VERSION 5.7 ;
BUSBITCHARS "[]" ;
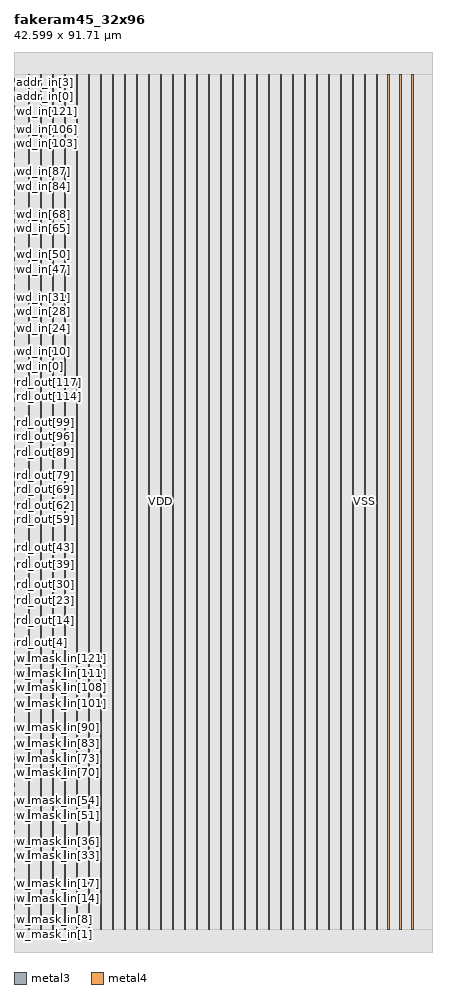
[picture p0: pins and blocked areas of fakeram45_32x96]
MACRO fakeram45_32x96
  FOREIGN fakeram45_32x96 0 0 ;
  SYMMETRY X Y R90 ;
  SIZE 42.599 BY 91.710 ;
  CLASS BLOCK ;
  PIN w_mask_in[0]
    DIRECTION INPUT ;
    USE SIGNAL ;
    SHAPE ABUTMENT ;
    PORT
      LAYER metal3 ;
      RECT 0.000 2.280 0.038 2.338 ;
    END
  END w_mask_in[0]
  PIN w_mask_in[1]
    DIRECTION INPUT ;
    USE SIGNAL ;
    SHAPE ABUTMENT ;
    PORT
      LAYER metal3 ;
      RECT 0.000 2.508 0.038 2.566 ;
    END
  END w_mask_in[1]
  PIN w_mask_in[2]
    DIRECTION INPUT ;
    USE SIGNAL ;
    SHAPE ABUTMENT ;
    PORT
      LAYER metal3 ;
      RECT 0.000 2.736 0.038 2.794 ;
    END
  END w_mask_in[2]
  PIN w_mask_in[3]
    DIRECTION INPUT ;
    USE SIGNAL ;
    SHAPE ABUTMENT ;
    PORT
      LAYER metal3 ;
      RECT 0.000 2.964 0.038 3.022 ;
    END
  END w_mask_in[3]
  PIN w_mask_in[4]
    DIRECTION INPUT ;
    USE SIGNAL ;
    SHAPE ABUTMENT ;
    PORT
      LAYER metal3 ;
      RECT 0.000 3.192 0.038 3.250 ;
    END
  END w_mask_in[4]
  PIN w_mask_in[5]
    DIRECTION INPUT ;
    USE SIGNAL ;
    SHAPE ABUTMENT ;
    PORT
      LAYER metal3 ;
      RECT 0.000 3.421 0.038 3.478 ;
    END
  END w_mask_in[5]
  PIN w_mask_in[6]
    DIRECTION INPUT ;
    USE SIGNAL ;
    SHAPE ABUTMENT ;
    PORT
      LAYER metal3 ;
      RECT 0.000 3.649 0.038 3.706 ;
    END
  END w_mask_in[6]
  PIN w_mask_in[7]
    DIRECTION INPUT ;
    USE SIGNAL ;
    SHAPE ABUTMENT ;
    PORT
      LAYER metal3 ;
      RECT 0.000 3.877 0.038 3.934 ;
    END
  END w_mask_in[7]
  PIN w_mask_in[8]
    DIRECTION INPUT ;
    USE SIGNAL ;
    SHAPE ABUTMENT ;
    PORT
      LAYER metal3 ;
      RECT 0.000 4.105 0.038 4.162 ;
    END
  END w_mask_in[8]
  PIN w_mask_in[9]
    DIRECTION INPUT ;
    USE SIGNAL ;
    SHAPE ABUTMENT ;
    PORT
      LAYER metal3 ;
      RECT 0.000 4.333 0.038 4.390 ;
    END
  END w_mask_in[9]
  PIN w_mask_in[10]
    DIRECTION INPUT ;
    USE SIGNAL ;
    SHAPE ABUTMENT ;
    PORT
      LAYER metal3 ;
      RECT 0.000 4.561 0.038 4.618 ;
    END
  END w_mask_in[10]
  PIN w_mask_in[11]
    DIRECTION INPUT ;
    USE SIGNAL ;
    SHAPE ABUTMENT ;
    PORT
      LAYER metal3 ;
      RECT 0.000 4.789 0.038 4.846 ;
    END
  END w_mask_in[11]
  PIN w_mask_in[12]
    DIRECTION INPUT ;
    USE SIGNAL ;
    SHAPE ABUTMENT ;
    PORT
      LAYER metal3 ;
      RECT 0.000 5.017 0.038 5.074 ;
    END
  END w_mask_in[12]
  PIN w_mask_in[13]
    DIRECTION INPUT ;
    USE SIGNAL ;
    SHAPE ABUTMENT ;
    PORT
      LAYER metal3 ;
      RECT 0.000 5.245 0.038 5.302 ;
    END
  END w_mask_in[13]
  PIN w_mask_in[14]
    DIRECTION INPUT ;
    USE SIGNAL ;
    SHAPE ABUTMENT ;
    PORT
      LAYER metal3 ;
      RECT 0.000 5.474 0.038 5.530 ;
    END
  END w_mask_in[14]
  PIN w_mask_in[15]
    DIRECTION INPUT ;
    USE SIGNAL ;
    SHAPE ABUTMENT ;
    PORT
      LAYER metal3 ;
      RECT 0.000 5.702 0.038 5.758 ;
    END
  END w_mask_in[15]
  PIN w_mask_in[16]
    DIRECTION INPUT ;
    USE SIGNAL ;
    SHAPE ABUTMENT ;
    PORT
      LAYER metal3 ;
      RECT 0.000 5.930 0.038 5.986 ;
    END
  END w_mask_in[16]
  PIN w_mask_in[17]
    DIRECTION INPUT ;
    USE SIGNAL ;
    SHAPE ABUTMENT ;
    PORT
      LAYER metal3 ;
      RECT 0.000 6.158 0.038 6.214 ;
    END
  END w_mask_in[17]
  PIN w_mask_in[18]
    DIRECTION INPUT ;
    USE SIGNAL ;
    SHAPE ABUTMENT ;
    PORT
      LAYER metal3 ;
      RECT 0.000 6.386 0.038 6.443 ;
    END
  END w_mask_in[18]
  PIN w_mask_in[19]
    DIRECTION INPUT ;
    USE SIGNAL ;
    SHAPE ABUTMENT ;
    PORT
      LAYER metal3 ;
      RECT 0.000 6.613 0.038 6.671 ;
    END
  END w_mask_in[19]
  PIN w_mask_in[20]
    DIRECTION INPUT ;
    USE SIGNAL ;
    SHAPE ABUTMENT ;
    PORT
      LAYER metal3 ;
      RECT 0.000 6.841 0.038 6.899 ;
    END
  END w_mask_in[20]
  PIN w_mask_in[21]
    DIRECTION INPUT ;
    USE SIGNAL ;
    SHAPE ABUTMENT ;
    PORT
      LAYER metal3 ;
      RECT 0.000 7.069 0.038 7.127 ;
    END
  END w_mask_in[21]
  PIN w_mask_in[22]
    DIRECTION INPUT ;
    USE SIGNAL ;
    SHAPE ABUTMENT ;
    PORT
      LAYER metal3 ;
      RECT 0.000 7.297 0.038 7.355 ;
    END
  END w_mask_in[22]
  PIN w_mask_in[23]
    DIRECTION INPUT ;
    USE SIGNAL ;
    SHAPE ABUTMENT ;
    PORT
      LAYER metal3 ;
      RECT 0.000 7.526 0.038 7.583 ;
    END
  END w_mask_in[23]
  PIN w_mask_in[24]
    DIRECTION INPUT ;
    USE SIGNAL ;
    SHAPE ABUTMENT ;
    PORT
      LAYER metal3 ;
      RECT 0.000 7.754 0.038 7.811 ;
    END
  END w_mask_in[24]
  PIN w_mask_in[25]
    DIRECTION INPUT ;
    USE SIGNAL ;
    SHAPE ABUTMENT ;
    PORT
      LAYER metal3 ;
      RECT 0.000 7.982 0.038 8.039 ;
    END
  END w_mask_in[25]
  PIN w_mask_in[26]
    DIRECTION INPUT ;
    USE SIGNAL ;
    SHAPE ABUTMENT ;
    PORT
      LAYER metal3 ;
      RECT 0.000 8.210 0.038 8.267 ;
    END
  END w_mask_in[26]
  PIN w_mask_in[27]
    DIRECTION INPUT ;
    USE SIGNAL ;
    SHAPE ABUTMENT ;
    PORT
      LAYER metal3 ;
      RECT 0.000 8.438 0.038 8.495 ;
    END
  END w_mask_in[27]
  PIN w_mask_in[28]
    DIRECTION INPUT ;
    USE SIGNAL ;
    SHAPE ABUTMENT ;
    PORT
      LAYER metal3 ;
      RECT 0.000 8.666 0.038 8.723 ;
    END
  END w_mask_in[28]
  PIN w_mask_in[29]
    DIRECTION INPUT ;
    USE SIGNAL ;
    SHAPE ABUTMENT ;
    PORT
      LAYER metal3 ;
      RECT 0.000 8.894 0.038 8.951 ;
    END
  END w_mask_in[29]
  PIN w_mask_in[30]
    DIRECTION INPUT ;
    USE SIGNAL ;
    SHAPE ABUTMENT ;
    PORT
      LAYER metal3 ;
      RECT 0.000 9.122 0.038 9.179 ;
    END
  END w_mask_in[30]
  PIN w_mask_in[31]
    DIRECTION INPUT ;
    USE SIGNAL ;
    SHAPE ABUTMENT ;
    PORT
      LAYER metal3 ;
      RECT 0.000 9.350 0.038 9.407 ;
    END
  END w_mask_in[31]
  PIN w_mask_in[32]
    DIRECTION INPUT ;
    USE SIGNAL ;
    SHAPE ABUTMENT ;
    PORT
      LAYER metal3 ;
      RECT 0.000 9.578 0.038 9.635 ;
    END
  END w_mask_in[32]
  PIN w_mask_in[33]
    DIRECTION INPUT ;
    USE SIGNAL ;
    SHAPE ABUTMENT ;
    PORT
      LAYER metal3 ;
      RECT 0.000 9.807 0.038 9.863 ;
    END
  END w_mask_in[33]
  PIN w_mask_in[34]
    DIRECTION INPUT ;
    USE SIGNAL ;
    SHAPE ABUTMENT ;
    PORT
      LAYER metal3 ;
      RECT 0.000 10.035 0.038 10.091 ;
    END
  END w_mask_in[34]
  PIN w_mask_in[35]
    DIRECTION INPUT ;
    USE SIGNAL ;
    SHAPE ABUTMENT ;
    PORT
      LAYER metal3 ;
      RECT 0.000 10.263 0.038 10.319 ;
    END
  END w_mask_in[35]
  PIN w_mask_in[36]
    DIRECTION INPUT ;
    USE SIGNAL ;
    SHAPE ABUTMENT ;
    PORT
      LAYER metal3 ;
      RECT 0.000 10.491 0.038 10.547 ;
    END
  END w_mask_in[36]
  PIN w_mask_in[37]
    DIRECTION INPUT ;
    USE SIGNAL ;
    SHAPE ABUTMENT ;
    PORT
      LAYER metal3 ;
      RECT 0.000 10.718 0.038 10.776 ;
    END
  END w_mask_in[37]
  PIN w_mask_in[38]
    DIRECTION INPUT ;
    USE SIGNAL ;
    SHAPE ABUTMENT ;
    PORT
      LAYER metal3 ;
      RECT 0.000 10.946 0.038 11.004 ;
    END
  END w_mask_in[38]
  PIN w_mask_in[39]
    DIRECTION INPUT ;
    USE SIGNAL ;
    SHAPE ABUTMENT ;
    PORT
      LAYER metal3 ;
      RECT 0.000 11.174 0.038 11.232 ;
    END
  END w_mask_in[39]
  PIN w_mask_in[40]
    DIRECTION INPUT ;
    USE SIGNAL ;
    SHAPE ABUTMENT ;
    PORT
      LAYER metal3 ;
      RECT 0.000 11.402 0.038 11.460 ;
    END
  END w_mask_in[40]
  PIN w_mask_in[41]
    DIRECTION INPUT ;
    USE SIGNAL ;
    SHAPE ABUTMENT ;
    PORT
      LAYER metal3 ;
      RECT 0.000 11.630 0.038 11.688 ;
    END
  END w_mask_in[41]
  PIN w_mask_in[42]
    DIRECTION INPUT ;
    USE SIGNAL ;
    SHAPE ABUTMENT ;
    PORT
      LAYER metal3 ;
      RECT 0.000 11.859 0.038 11.916 ;
    END
  END w_mask_in[42]
  PIN w_mask_in[43]
    DIRECTION INPUT ;
    USE SIGNAL ;
    SHAPE ABUTMENT ;
    PORT
      LAYER metal3 ;
      RECT 0.000 12.087 0.038 12.144 ;
    END
  END w_mask_in[43]
  PIN w_mask_in[44]
    DIRECTION INPUT ;
    USE SIGNAL ;
    SHAPE ABUTMENT ;
    PORT
      LAYER metal3 ;
      RECT 0.000 12.315 0.038 12.372 ;
    END
  END w_mask_in[44]
  PIN w_mask_in[45]
    DIRECTION INPUT ;
    USE SIGNAL ;
    SHAPE ABUTMENT ;
    PORT
      LAYER metal3 ;
      RECT 0.000 12.543 0.038 12.600 ;
    END
  END w_mask_in[45]
  PIN w_mask_in[46]
    DIRECTION INPUT ;
    USE SIGNAL ;
    SHAPE ABUTMENT ;
    PORT
      LAYER metal3 ;
      RECT 0.000 12.771 0.038 12.828 ;
    END
  END w_mask_in[46]
  PIN w_mask_in[47]
    DIRECTION INPUT ;
    USE SIGNAL ;
    SHAPE ABUTMENT ;
    PORT
      LAYER metal3 ;
      RECT 0.000 12.999 0.038 13.056 ;
    END
  END w_mask_in[47]
  PIN w_mask_in[48]
    DIRECTION INPUT ;
    USE SIGNAL ;
    SHAPE ABUTMENT ;
    PORT
      LAYER metal3 ;
      RECT 0.000 13.227 0.038 13.284 ;
    END
  END w_mask_in[48]
  PIN w_mask_in[49]
    DIRECTION INPUT ;
    USE SIGNAL ;
    SHAPE ABUTMENT ;
    PORT
      LAYER metal3 ;
      RECT 0.000 13.455 0.038 13.512 ;
    END
  END w_mask_in[49]
  PIN w_mask_in[50]
    DIRECTION INPUT ;
    USE SIGNAL ;
    SHAPE ABUTMENT ;
    PORT
      LAYER metal3 ;
      RECT 0.000 13.683 0.038 13.740 ;
    END
  END w_mask_in[50]
  PIN w_mask_in[51]
    DIRECTION INPUT ;
    USE SIGNAL ;
    SHAPE ABUTMENT ;
    PORT
      LAYER metal3 ;
      RECT 0.000 13.912 0.038 13.968 ;
    END
  END w_mask_in[51]
  PIN w_mask_in[52]
    DIRECTION INPUT ;
    USE SIGNAL ;
    SHAPE ABUTMENT ;
    PORT
      LAYER metal3 ;
      RECT 0.000 14.140 0.038 14.196 ;
    END
  END w_mask_in[52]
  PIN w_mask_in[53]
    DIRECTION INPUT ;
    USE SIGNAL ;
    SHAPE ABUTMENT ;
    PORT
      LAYER metal3 ;
      RECT 0.000 14.368 0.038 14.424 ;
    END
  END w_mask_in[53]
  PIN w_mask_in[54]
    DIRECTION INPUT ;
    USE SIGNAL ;
    SHAPE ABUTMENT ;
    PORT
      LAYER metal3 ;
      RECT 0.000 14.596 0.038 14.652 ;
    END
  END w_mask_in[54]
  PIN w_mask_in[55]
    DIRECTION INPUT ;
    USE SIGNAL ;
    SHAPE ABUTMENT ;
    PORT
      LAYER metal3 ;
      RECT 0.000 14.824 0.038 14.880 ;
    END
  END w_mask_in[55]
  PIN w_mask_in[56]
    DIRECTION INPUT ;
    USE SIGNAL ;
    SHAPE ABUTMENT ;
    PORT
      LAYER metal3 ;
      RECT 0.000 15.051 0.038 15.109 ;
    END
  END w_mask_in[56]
  PIN w_mask_in[57]
    DIRECTION INPUT ;
    USE SIGNAL ;
    SHAPE ABUTMENT ;
    PORT
      LAYER metal3 ;
      RECT 0.000 15.279 0.038 15.337 ;
    END
  END w_mask_in[57]
  PIN w_mask_in[58]
    DIRECTION INPUT ;
    USE SIGNAL ;
    SHAPE ABUTMENT ;
    PORT
      LAYER metal3 ;
      RECT 0.000 15.507 0.038 15.565 ;
    END
  END w_mask_in[58]
  PIN w_mask_in[59]
    DIRECTION INPUT ;
    USE SIGNAL ;
    SHAPE ABUTMENT ;
    PORT
      LAYER metal3 ;
      RECT 0.000 15.735 0.038 15.793 ;
    END
  END w_mask_in[59]
  PIN w_mask_in[60]
    DIRECTION INPUT ;
    USE SIGNAL ;
    SHAPE ABUTMENT ;
    PORT
      LAYER metal3 ;
      RECT 0.000 15.963 0.038 16.021 ;
    END
  END w_mask_in[60]
  PIN w_mask_in[61]
    DIRECTION INPUT ;
    USE SIGNAL ;
    SHAPE ABUTMENT ;
    PORT
      LAYER metal3 ;
      RECT 0.000 16.192 0.038 16.249 ;
    END
  END w_mask_in[61]
  PIN w_mask_in[62]
    DIRECTION INPUT ;
    USE SIGNAL ;
    SHAPE ABUTMENT ;
    PORT
      LAYER metal3 ;
      RECT 0.000 16.420 0.038 16.477 ;
    END
  END w_mask_in[62]
  PIN w_mask_in[63]
    DIRECTION INPUT ;
    USE SIGNAL ;
    SHAPE ABUTMENT ;
    PORT
      LAYER metal3 ;
      RECT 0.000 16.648 0.038 16.705 ;
    END
  END w_mask_in[63]
  PIN w_mask_in[64]
    DIRECTION INPUT ;
    USE SIGNAL ;
    SHAPE ABUTMENT ;
    PORT
      LAYER metal3 ;
      RECT 0.000 16.876 0.038 16.933 ;
    END
  END w_mask_in[64]
  PIN w_mask_in[65]
    DIRECTION INPUT ;
    USE SIGNAL ;
    SHAPE ABUTMENT ;
    PORT
      LAYER metal3 ;
      RECT 0.000 17.104 0.038 17.161 ;
    END
  END w_mask_in[65]
  PIN w_mask_in[66]
    DIRECTION INPUT ;
    USE SIGNAL ;
    SHAPE ABUTMENT ;
    PORT
      LAYER metal3 ;
      RECT 0.000 17.332 0.038 17.389 ;
    END
  END w_mask_in[66]
  PIN w_mask_in[67]
    DIRECTION INPUT ;
    USE SIGNAL ;
    SHAPE ABUTMENT ;
    PORT
      LAYER metal3 ;
      RECT 0.000 17.560 0.038 17.617 ;
    END
  END w_mask_in[67]
  PIN w_mask_in[68]
    DIRECTION INPUT ;
    USE SIGNAL ;
    SHAPE ABUTMENT ;
    PORT
      LAYER metal3 ;
      RECT 0.000 17.788 0.038 17.845 ;
    END
  END w_mask_in[68]
  PIN w_mask_in[69]
    DIRECTION INPUT ;
    USE SIGNAL ;
    SHAPE ABUTMENT ;
    PORT
      LAYER metal3 ;
      RECT 0.000 18.016 0.038 18.073 ;
    END
  END w_mask_in[69]
  PIN w_mask_in[70]
    DIRECTION INPUT ;
    USE SIGNAL ;
    SHAPE ABUTMENT ;
    PORT
      LAYER metal3 ;
      RECT 0.000 18.245 0.038 18.301 ;
    END
  END w_mask_in[70]
  PIN w_mask_in[71]
    DIRECTION INPUT ;
    USE SIGNAL ;
    SHAPE ABUTMENT ;
    PORT
      LAYER metal3 ;
      RECT 0.000 18.473 0.038 18.529 ;
    END
  END w_mask_in[71]
  PIN w_mask_in[72]
    DIRECTION INPUT ;
    USE SIGNAL ;
    SHAPE ABUTMENT ;
    PORT
      LAYER metal3 ;
      RECT 0.000 18.701 0.038 18.757 ;
    END
  END w_mask_in[72]
  PIN w_mask_in[73]
    DIRECTION INPUT ;
    USE SIGNAL ;
    SHAPE ABUTMENT ;
    PORT
      LAYER metal3 ;
      RECT 0.000 18.929 0.038 18.985 ;
    END
  END w_mask_in[73]
  PIN w_mask_in[74]
    DIRECTION INPUT ;
    USE SIGNAL ;
    SHAPE ABUTMENT ;
    PORT
      LAYER metal3 ;
      RECT 0.000 19.157 0.038 19.214 ;
    END
  END w_mask_in[74]
  PIN w_mask_in[75]
    DIRECTION INPUT ;
    USE SIGNAL ;
    SHAPE ABUTMENT ;
    PORT
      LAYER metal3 ;
      RECT 0.000 19.384 0.038 19.442 ;
    END
  END w_mask_in[75]
  PIN w_mask_in[76]
    DIRECTION INPUT ;
    USE SIGNAL ;
    SHAPE ABUTMENT ;
    PORT
      LAYER metal3 ;
      RECT 0.000 19.612 0.038 19.670 ;
    END
  END w_mask_in[76]
  PIN w_mask_in[77]
    DIRECTION INPUT ;
    USE SIGNAL ;
    SHAPE ABUTMENT ;
    PORT
      LAYER metal3 ;
      RECT 0.000 19.840 0.038 19.898 ;
    END
  END w_mask_in[77]
  PIN w_mask_in[78]
    DIRECTION INPUT ;
    USE SIGNAL ;
    SHAPE ABUTMENT ;
    PORT
      LAYER metal3 ;
      RECT 0.000 20.068 0.038 20.126 ;
    END
  END w_mask_in[78]
  PIN w_mask_in[79]
    DIRECTION INPUT ;
    USE SIGNAL ;
    SHAPE ABUTMENT ;
    PORT
      LAYER metal3 ;
      RECT 0.000 20.297 0.038 20.354 ;
    END
  END w_mask_in[79]
  PIN w_mask_in[80]
    DIRECTION INPUT ;
    USE SIGNAL ;
    SHAPE ABUTMENT ;
    PORT
      LAYER metal3 ;
      RECT 0.000 20.525 0.038 20.582 ;
    END
  END w_mask_in[80]
  PIN w_mask_in[81]
    DIRECTION INPUT ;
    USE SIGNAL ;
    SHAPE ABUTMENT ;
    PORT
      LAYER metal3 ;
      RECT 0.000 20.753 0.038 20.810 ;
    END
  END w_mask_in[81]
  PIN w_mask_in[82]
    DIRECTION INPUT ;
    USE SIGNAL ;
    SHAPE ABUTMENT ;
    PORT
      LAYER metal3 ;
      RECT 0.000 20.981 0.038 21.038 ;
    END
  END w_mask_in[82]
  PIN w_mask_in[83]
    DIRECTION INPUT ;
    USE SIGNAL ;
    SHAPE ABUTMENT ;
    PORT
      LAYER metal3 ;
      RECT 0.000 21.209 0.038 21.266 ;
    END
  END w_mask_in[83]
  PIN w_mask_in[84]
    DIRECTION INPUT ;
    USE SIGNAL ;
    SHAPE ABUTMENT ;
    PORT
      LAYER metal3 ;
      RECT 0.000 21.437 0.038 21.494 ;
    END
  END w_mask_in[84]
  PIN w_mask_in[85]
    DIRECTION INPUT ;
    USE SIGNAL ;
    SHAPE ABUTMENT ;
    PORT
      LAYER metal3 ;
      RECT 0.000 21.665 0.038 21.722 ;
    END
  END w_mask_in[85]
  PIN w_mask_in[86]
    DIRECTION INPUT ;
    USE SIGNAL ;
    SHAPE ABUTMENT ;
    PORT
      LAYER metal3 ;
      RECT 0.000 21.893 0.038 21.950 ;
    END
  END w_mask_in[86]
  PIN w_mask_in[87]
    DIRECTION INPUT ;
    USE SIGNAL ;
    SHAPE ABUTMENT ;
    PORT
      LAYER metal3 ;
      RECT 0.000 22.121 0.038 22.178 ;
    END
  END w_mask_in[87]
  PIN w_mask_in[88]
    DIRECTION INPUT ;
    USE SIGNAL ;
    SHAPE ABUTMENT ;
    PORT
      LAYER metal3 ;
      RECT 0.000 22.349 0.038 22.406 ;
    END
  END w_mask_in[88]
  PIN w_mask_in[89]
    DIRECTION INPUT ;
    USE SIGNAL ;
    SHAPE ABUTMENT ;
    PORT
      LAYER metal3 ;
      RECT 0.000 22.578 0.038 22.634 ;
    END
  END w_mask_in[89]
  PIN w_mask_in[90]
    DIRECTION INPUT ;
    USE SIGNAL ;
    SHAPE ABUTMENT ;
    PORT
      LAYER metal3 ;
      RECT 0.000 22.806 0.038 22.862 ;
    END
  END w_mask_in[90]
  PIN w_mask_in[91]
    DIRECTION INPUT ;
    USE SIGNAL ;
    SHAPE ABUTMENT ;
    PORT
      LAYER metal3 ;
      RECT 0.000 23.034 0.038 23.090 ;
    END
  END w_mask_in[91]
  PIN w_mask_in[92]
    DIRECTION INPUT ;
    USE SIGNAL ;
    SHAPE ABUTMENT ;
    PORT
      LAYER metal3 ;
      RECT 0.000 23.262 0.038 23.318 ;
    END
  END w_mask_in[92]
  PIN w_mask_in[93]
    DIRECTION INPUT ;
    USE SIGNAL ;
    SHAPE ABUTMENT ;
    PORT
      LAYER metal3 ;
      RECT 0.000 23.490 0.038 23.547 ;
    END
  END w_mask_in[93]
  PIN w_mask_in[94]
    DIRECTION INPUT ;
    USE SIGNAL ;
    SHAPE ABUTMENT ;
    PORT
      LAYER metal3 ;
      RECT 0.000 23.717 0.038 23.775 ;
    END
  END w_mask_in[94]
  PIN w_mask_in[95]
    DIRECTION INPUT ;
    USE SIGNAL ;
    SHAPE ABUTMENT ;
    PORT
      LAYER metal3 ;
      RECT 0.000 23.945 0.038 24.003 ;
    END
  END w_mask_in[95]
  PIN w_mask_in[96]
    DIRECTION INPUT ;
    USE SIGNAL ;
    SHAPE ABUTMENT ;
    PORT
      LAYER metal3 ;
      RECT 0.000 24.173 0.038 24.231 ;
    END
  END w_mask_in[96]
  PIN w_mask_in[97]
    DIRECTION INPUT ;
    USE SIGNAL ;
    SHAPE ABUTMENT ;
    PORT
      LAYER metal3 ;
      RECT 0.000 24.401 0.038 24.459 ;
    END
  END w_mask_in[97]
  PIN w_mask_in[98]
    DIRECTION INPUT ;
    USE SIGNAL ;
    SHAPE ABUTMENT ;
    PORT
      LAYER metal3 ;
      RECT 0.000 24.630 0.038 24.687 ;
    END
  END w_mask_in[98]
  PIN w_mask_in[99]
    DIRECTION INPUT ;
    USE SIGNAL ;
    SHAPE ABUTMENT ;
    PORT
      LAYER metal3 ;
      RECT 0.000 24.858 0.038 24.915 ;
    END
  END w_mask_in[99]
  PIN w_mask_in[100]
    DIRECTION INPUT ;
    USE SIGNAL ;
    SHAPE ABUTMENT ;
    PORT
      LAYER metal3 ;
      RECT 0.000 25.086 0.038 25.143 ;
    END
  END w_mask_in[100]
  PIN w_mask_in[101]
    DIRECTION INPUT ;
    USE SIGNAL ;
    SHAPE ABUTMENT ;
    PORT
      LAYER metal3 ;
      RECT 0.000 25.314 0.038 25.371 ;
    END
  END w_mask_in[101]
  PIN w_mask_in[102]
    DIRECTION INPUT ;
    USE SIGNAL ;
    SHAPE ABUTMENT ;
    PORT
      LAYER metal3 ;
      RECT 0.000 25.542 0.038 25.599 ;
    END
  END w_mask_in[102]
  PIN w_mask_in[103]
    DIRECTION INPUT ;
    USE SIGNAL ;
    SHAPE ABUTMENT ;
    PORT
      LAYER metal3 ;
      RECT 0.000 25.770 0.038 25.827 ;
    END
  END w_mask_in[103]
  PIN w_mask_in[104]
    DIRECTION INPUT ;
    USE SIGNAL ;
    SHAPE ABUTMENT ;
    PORT
      LAYER metal3 ;
      RECT 0.000 25.998 0.038 26.055 ;
    END
  END w_mask_in[104]
  PIN w_mask_in[105]
    DIRECTION INPUT ;
    USE SIGNAL ;
    SHAPE ABUTMENT ;
    PORT
      LAYER metal3 ;
      RECT 0.000 26.226 0.038 26.283 ;
    END
  END w_mask_in[105]
  PIN w_mask_in[106]
    DIRECTION INPUT ;
    USE SIGNAL ;
    SHAPE ABUTMENT ;
    PORT
      LAYER metal3 ;
      RECT 0.000 26.454 0.038 26.511 ;
    END
  END w_mask_in[106]
  PIN w_mask_in[107]
    DIRECTION INPUT ;
    USE SIGNAL ;
    SHAPE ABUTMENT ;
    PORT
      LAYER metal3 ;
      RECT 0.000 26.683 0.038 26.739 ;
    END
  END w_mask_in[107]
  PIN w_mask_in[108]
    DIRECTION INPUT ;
    USE SIGNAL ;
    SHAPE ABUTMENT ;
    PORT
      LAYER metal3 ;
      RECT 0.000 26.911 0.038 26.967 ;
    END
  END w_mask_in[108]
  PIN w_mask_in[109]
    DIRECTION INPUT ;
    USE SIGNAL ;
    SHAPE ABUTMENT ;
    PORT
      LAYER metal3 ;
      RECT 0.000 27.139 0.038 27.195 ;
    END
  END w_mask_in[109]
  PIN w_mask_in[110]
    DIRECTION INPUT ;
    USE SIGNAL ;
    SHAPE ABUTMENT ;
    PORT
      LAYER metal3 ;
      RECT 0.000 27.367 0.038 27.423 ;
    END
  END w_mask_in[110]
  PIN w_mask_in[111]
    DIRECTION INPUT ;
    USE SIGNAL ;
    SHAPE ABUTMENT ;
    PORT
      LAYER metal3 ;
      RECT 0.000 27.595 0.038 27.651 ;
    END
  END w_mask_in[111]
  PIN w_mask_in[112]
    DIRECTION INPUT ;
    USE SIGNAL ;
    SHAPE ABUTMENT ;
    PORT
      LAYER metal3 ;
      RECT 0.000 27.823 0.038 27.880 ;
    END
  END w_mask_in[112]
  PIN w_mask_in[113]
    DIRECTION INPUT ;
    USE SIGNAL ;
    SHAPE ABUTMENT ;
    PORT
      LAYER metal3 ;
      RECT 0.000 28.050 0.038 28.108 ;
    END
  END w_mask_in[113]
  PIN w_mask_in[114]
    DIRECTION INPUT ;
    USE SIGNAL ;
    SHAPE ABUTMENT ;
    PORT
      LAYER metal3 ;
      RECT 0.000 28.278 0.038 28.336 ;
    END
  END w_mask_in[114]
  PIN w_mask_in[115]
    DIRECTION INPUT ;
    USE SIGNAL ;
    SHAPE ABUTMENT ;
    PORT
      LAYER metal3 ;
      RECT 0.000 28.506 0.038 28.564 ;
    END
  END w_mask_in[115]
  PIN w_mask_in[116]
    DIRECTION INPUT ;
    USE SIGNAL ;
    SHAPE ABUTMENT ;
    PORT
      LAYER metal3 ;
      RECT 0.000 28.734 0.038 28.792 ;
    END
  END w_mask_in[116]
  PIN w_mask_in[117]
    DIRECTION INPUT ;
    USE SIGNAL ;
    SHAPE ABUTMENT ;
    PORT
      LAYER metal3 ;
      RECT 0.000 28.963 0.038 29.020 ;
    END
  END w_mask_in[117]
  PIN w_mask_in[118]
    DIRECTION INPUT ;
    USE SIGNAL ;
    SHAPE ABUTMENT ;
    PORT
      LAYER metal3 ;
      RECT 0.000 29.191 0.038 29.248 ;
    END
  END w_mask_in[118]
  PIN w_mask_in[119]
    DIRECTION INPUT ;
    USE SIGNAL ;
    SHAPE ABUTMENT ;
    PORT
      LAYER metal3 ;
      RECT 0.000 29.419 0.038 29.476 ;
    END
  END w_mask_in[119]
  PIN w_mask_in[120]
    DIRECTION INPUT ;
    USE SIGNAL ;
    SHAPE ABUTMENT ;
    PORT
      LAYER metal3 ;
      RECT 0.000 29.647 0.038 29.704 ;
    END
  END w_mask_in[120]
  PIN w_mask_in[121]
    DIRECTION INPUT ;
    USE SIGNAL ;
    SHAPE ABUTMENT ;
    PORT
      LAYER metal3 ;
      RECT 0.000 29.875 0.038 29.932 ;
    END
  END w_mask_in[121]
  PIN w_mask_in[122]
    DIRECTION INPUT ;
    USE SIGNAL ;
    SHAPE ABUTMENT ;
    PORT
      LAYER metal3 ;
      RECT 0.000 30.103 0.038 30.160 ;
    END
  END w_mask_in[122]
  PIN w_mask_in[123]
    DIRECTION INPUT ;
    USE SIGNAL ;
    SHAPE ABUTMENT ;
    PORT
      LAYER metal3 ;
      RECT 0.000 30.331 0.038 30.388 ;
    END
  END w_mask_in[123]
  PIN rd_out[0]
    DIRECTION OUTPUT ;
    USE SIGNAL ;
    SHAPE ABUTMENT ;
    PORT
      LAYER metal3 ;
      RECT 0.000 30.559 0.038 30.616 ;
    END
  END rd_out[0]
  PIN rd_out[1]
    DIRECTION OUTPUT ;
    USE SIGNAL ;
    SHAPE ABUTMENT ;
    PORT
      LAYER metal3 ;
      RECT 0.000 30.787 0.038 30.844 ;
    END
  END rd_out[1]
  PIN rd_out[2]
    DIRECTION OUTPUT ;
    USE SIGNAL ;
    SHAPE ABUTMENT ;
    PORT
      LAYER metal3 ;
      RECT 0.000 31.016 0.038 31.072 ;
    END
  END rd_out[2]
  PIN rd_out[3]
    DIRECTION OUTPUT ;
    USE SIGNAL ;
    SHAPE ABUTMENT ;
    PORT
      LAYER metal3 ;
      RECT 0.000 31.244 0.038 31.300 ;
    END
  END rd_out[3]
  PIN rd_out[4]
    DIRECTION OUTPUT ;
    USE SIGNAL ;
    SHAPE ABUTMENT ;
    PORT
      LAYER metal3 ;
      RECT 0.000 31.472 0.038 31.528 ;
    END
  END rd_out[4]
  PIN rd_out[5]
    DIRECTION OUTPUT ;
    USE SIGNAL ;
    SHAPE ABUTMENT ;
    PORT
      LAYER metal3 ;
      RECT 0.000 31.700 0.038 31.756 ;
    END
  END rd_out[5]
  PIN rd_out[6]
    DIRECTION OUTPUT ;
    USE SIGNAL ;
    SHAPE ABUTMENT ;
    PORT
      LAYER metal3 ;
      RECT 0.000 31.928 0.038 31.984 ;
    END
  END rd_out[6]
  PIN rd_out[7]
    DIRECTION OUTPUT ;
    USE SIGNAL ;
    SHAPE ABUTMENT ;
    PORT
      LAYER metal3 ;
      RECT 0.000 32.155 0.038 32.213 ;
    END
  END rd_out[7]
  PIN rd_out[8]
    DIRECTION OUTPUT ;
    USE SIGNAL ;
    SHAPE ABUTMENT ;
    PORT
      LAYER metal3 ;
      RECT 0.000 32.383 0.038 32.441 ;
    END
  END rd_out[8]
  PIN rd_out[9]
    DIRECTION OUTPUT ;
    USE SIGNAL ;
    SHAPE ABUTMENT ;
    PORT
      LAYER metal3 ;
      RECT 0.000 32.611 0.038 32.669 ;
    END
  END rd_out[9]
  PIN rd_out[10]
    DIRECTION OUTPUT ;
    USE SIGNAL ;
    SHAPE ABUTMENT ;
    PORT
      LAYER metal3 ;
      RECT 0.000 32.839 0.038 32.897 ;
    END
  END rd_out[10]
  PIN rd_out[11]
    DIRECTION OUTPUT ;
    USE SIGNAL ;
    SHAPE ABUTMENT ;
    PORT
      LAYER metal3 ;
      RECT 0.000 33.068 0.038 33.125 ;
    END
  END rd_out[11]
  PIN rd_out[12]
    DIRECTION OUTPUT ;
    USE SIGNAL ;
    SHAPE ABUTMENT ;
    PORT
      LAYER metal3 ;
      RECT 0.000 33.296 0.038 33.353 ;
    END
  END rd_out[12]
  PIN rd_out[13]
    DIRECTION OUTPUT ;
    USE SIGNAL ;
    SHAPE ABUTMENT ;
    PORT
      LAYER metal3 ;
      RECT 0.000 33.524 0.038 33.581 ;
    END
  END rd_out[13]
  PIN rd_out[14]
    DIRECTION OUTPUT ;
    USE SIGNAL ;
    SHAPE ABUTMENT ;
    PORT
      LAYER metal3 ;
      RECT 0.000 33.752 0.038 33.809 ;
    END
  END rd_out[14]
  PIN rd_out[15]
    DIRECTION OUTPUT ;
    USE SIGNAL ;
    SHAPE ABUTMENT ;
    PORT
      LAYER metal3 ;
      RECT 0.000 33.980 0.038 34.037 ;
    END
  END rd_out[15]
  PIN rd_out[16]
    DIRECTION OUTPUT ;
    USE SIGNAL ;
    SHAPE ABUTMENT ;
    PORT
      LAYER metal3 ;
      RECT 0.000 34.208 0.038 34.265 ;
    END
  END rd_out[16]
  PIN rd_out[17]
    DIRECTION OUTPUT ;
    USE SIGNAL ;
    SHAPE ABUTMENT ;
    PORT
      LAYER metal3 ;
      RECT 0.000 34.436 0.038 34.493 ;
    END
  END rd_out[17]
  PIN rd_out[18]
    DIRECTION OUTPUT ;
    USE SIGNAL ;
    SHAPE ABUTMENT ;
    PORT
      LAYER metal3 ;
      RECT 0.000 34.664 0.038 34.721 ;
    END
  END rd_out[18]
  PIN rd_out[19]
    DIRECTION OUTPUT ;
    USE SIGNAL ;
    SHAPE ABUTMENT ;
    PORT
      LAYER metal3 ;
      RECT 0.000 34.892 0.038 34.949 ;
    END
  END rd_out[19]
  PIN rd_out[20]
    DIRECTION OUTPUT ;
    USE SIGNAL ;
    SHAPE ABUTMENT ;
    PORT
      LAYER metal3 ;
      RECT 0.000 35.120 0.038 35.177 ;
    END
  END rd_out[20]
  PIN rd_out[21]
    DIRECTION OUTPUT ;
    USE SIGNAL ;
    SHAPE ABUTMENT ;
    PORT
      LAYER metal3 ;
      RECT 0.000 35.349 0.038 35.405 ;
    END
  END rd_out[21]
  PIN rd_out[22]
    DIRECTION OUTPUT ;
    USE SIGNAL ;
    SHAPE ABUTMENT ;
    PORT
      LAYER metal3 ;
      RECT 0.000 35.577 0.038 35.633 ;
    END
  END rd_out[22]
  PIN rd_out[23]
    DIRECTION OUTPUT ;
    USE SIGNAL ;
    SHAPE ABUTMENT ;
    PORT
      LAYER metal3 ;
      RECT 0.000 35.805 0.038 35.861 ;
    END
  END rd_out[23]
  PIN rd_out[24]
    DIRECTION OUTPUT ;
    USE SIGNAL ;
    SHAPE ABUTMENT ;
    PORT
      LAYER metal3 ;
      RECT 0.000 36.033 0.038 36.089 ;
    END
  END rd_out[24]
  PIN rd_out[25]
    DIRECTION OUTPUT ;
    USE SIGNAL ;
    SHAPE ABUTMENT ;
    PORT
      LAYER metal3 ;
      RECT 0.000 36.261 0.038 36.318 ;
    END
  END rd_out[25]
  PIN rd_out[26]
    DIRECTION OUTPUT ;
    USE SIGNAL ;
    SHAPE ABUTMENT ;
    PORT
      LAYER metal3 ;
      RECT 0.000 36.488 0.038 36.546 ;
    END
  END rd_out[26]
  PIN rd_out[27]
    DIRECTION OUTPUT ;
    USE SIGNAL ;
    SHAPE ABUTMENT ;
    PORT
      LAYER metal3 ;
      RECT 0.000 36.716 0.038 36.774 ;
    END
  END rd_out[27]
  PIN rd_out[28]
    DIRECTION OUTPUT ;
    USE SIGNAL ;
    SHAPE ABUTMENT ;
    PORT
      LAYER metal3 ;
      RECT 0.000 36.944 0.038 37.002 ;
    END
  END rd_out[28]
  PIN rd_out[29]
    DIRECTION OUTPUT ;
    USE SIGNAL ;
    SHAPE ABUTMENT ;
    PORT
      LAYER metal3 ;
      RECT 0.000 37.172 0.038 37.230 ;
    END
  END rd_out[29]
  PIN rd_out[30]
    DIRECTION OUTPUT ;
    USE SIGNAL ;
    SHAPE ABUTMENT ;
    PORT
      LAYER metal3 ;
      RECT 0.000 37.401 0.038 37.458 ;
    END
  END rd_out[30]
  PIN rd_out[31]
    DIRECTION OUTPUT ;
    USE SIGNAL ;
    SHAPE ABUTMENT ;
    PORT
      LAYER metal3 ;
      RECT 0.000 37.629 0.038 37.686 ;
    END
  END rd_out[31]
  PIN rd_out[32]
    DIRECTION OUTPUT ;
    USE SIGNAL ;
    SHAPE ABUTMENT ;
    PORT
      LAYER metal3 ;
      RECT 0.000 37.857 0.038 37.914 ;
    END
  END rd_out[32]
  PIN rd_out[33]
    DIRECTION OUTPUT ;
    USE SIGNAL ;
    SHAPE ABUTMENT ;
    PORT
      LAYER metal3 ;
      RECT 0.000 38.085 0.038 38.142 ;
    END
  END rd_out[33]
  PIN rd_out[34]
    DIRECTION OUTPUT ;
    USE SIGNAL ;
    SHAPE ABUTMENT ;
    PORT
      LAYER metal3 ;
      RECT 0.000 38.313 0.038 38.370 ;
    END
  END rd_out[34]
  PIN rd_out[35]
    DIRECTION OUTPUT ;
    USE SIGNAL ;
    SHAPE ABUTMENT ;
    PORT
      LAYER metal3 ;
      RECT 0.000 38.541 0.038 38.598 ;
    END
  END rd_out[35]
  PIN rd_out[36]
    DIRECTION OUTPUT ;
    USE SIGNAL ;
    SHAPE ABUTMENT ;
    PORT
      LAYER metal3 ;
      RECT 0.000 38.769 0.038 38.826 ;
    END
  END rd_out[36]
  PIN rd_out[37]
    DIRECTION OUTPUT ;
    USE SIGNAL ;
    SHAPE ABUTMENT ;
    PORT
      LAYER metal3 ;
      RECT 0.000 38.997 0.038 39.054 ;
    END
  END rd_out[37]
  PIN rd_out[38]
    DIRECTION OUTPUT ;
    USE SIGNAL ;
    SHAPE ABUTMENT ;
    PORT
      LAYER metal3 ;
      RECT 0.000 39.225 0.038 39.282 ;
    END
  END rd_out[38]
  PIN rd_out[39]
    DIRECTION OUTPUT ;
    USE SIGNAL ;
    SHAPE ABUTMENT ;
    PORT
      LAYER metal3 ;
      RECT 0.000 39.454 0.038 39.510 ;
    END
  END rd_out[39]
  PIN rd_out[40]
    DIRECTION OUTPUT ;
    USE SIGNAL ;
    SHAPE ABUTMENT ;
    PORT
      LAYER metal3 ;
      RECT 0.000 39.682 0.038 39.738 ;
    END
  END rd_out[40]
  PIN rd_out[41]
    DIRECTION OUTPUT ;
    USE SIGNAL ;
    SHAPE ABUTMENT ;
    PORT
      LAYER metal3 ;
      RECT 0.000 39.910 0.038 39.966 ;
    END
  END rd_out[41]
  PIN rd_out[42]
    DIRECTION OUTPUT ;
    USE SIGNAL ;
    SHAPE ABUTMENT ;
    PORT
      LAYER metal3 ;
      RECT 0.000 40.138 0.038 40.194 ;
    END
  END rd_out[42]
  PIN rd_out[43]
    DIRECTION OUTPUT ;
    USE SIGNAL ;
    SHAPE ABUTMENT ;
    PORT
      LAYER metal3 ;
      RECT 0.000 40.366 0.038 40.422 ;
    END
  END rd_out[43]
  PIN rd_out[44]
    DIRECTION OUTPUT ;
    USE SIGNAL ;
    SHAPE ABUTMENT ;
    PORT
      LAYER metal3 ;
      RECT 0.000 40.594 0.038 40.651 ;
    END
  END rd_out[44]
  PIN rd_out[45]
    DIRECTION OUTPUT ;
    USE SIGNAL ;
    SHAPE ABUTMENT ;
    PORT
      LAYER metal3 ;
      RECT 0.000 40.821 0.038 40.879 ;
    END
  END rd_out[45]
  PIN rd_out[46]
    DIRECTION OUTPUT ;
    USE SIGNAL ;
    SHAPE ABUTMENT ;
    PORT
      LAYER metal3 ;
      RECT 0.000 41.049 0.038 41.107 ;
    END
  END rd_out[46]
  PIN rd_out[47]
    DIRECTION OUTPUT ;
    USE SIGNAL ;
    SHAPE ABUTMENT ;
    PORT
      LAYER metal3 ;
      RECT 0.000 41.277 0.038 41.335 ;
    END
  END rd_out[47]
  PIN rd_out[48]
    DIRECTION OUTPUT ;
    USE SIGNAL ;
    SHAPE ABUTMENT ;
    PORT
      LAYER metal3 ;
      RECT 0.000 41.505 0.038 41.563 ;
    END
  END rd_out[48]
  PIN rd_out[49]
    DIRECTION OUTPUT ;
    USE SIGNAL ;
    SHAPE ABUTMENT ;
    PORT
      LAYER metal3 ;
      RECT 0.000 41.734 0.038 41.791 ;
    END
  END rd_out[49]
  PIN rd_out[50]
    DIRECTION OUTPUT ;
    USE SIGNAL ;
    SHAPE ABUTMENT ;
    PORT
      LAYER metal3 ;
      RECT 0.000 41.962 0.038 42.019 ;
    END
  END rd_out[50]
  PIN rd_out[51]
    DIRECTION OUTPUT ;
    USE SIGNAL ;
    SHAPE ABUTMENT ;
    PORT
      LAYER metal3 ;
      RECT 0.000 42.190 0.038 42.247 ;
    END
  END rd_out[51]
  PIN rd_out[52]
    DIRECTION OUTPUT ;
    USE SIGNAL ;
    SHAPE ABUTMENT ;
    PORT
      LAYER metal3 ;
      RECT 0.000 42.418 0.038 42.475 ;
    END
  END rd_out[52]
  PIN rd_out[53]
    DIRECTION OUTPUT ;
    USE SIGNAL ;
    SHAPE ABUTMENT ;
    PORT
      LAYER metal3 ;
      RECT 0.000 42.646 0.038 42.703 ;
    END
  END rd_out[53]
  PIN rd_out[54]
    DIRECTION OUTPUT ;
    USE SIGNAL ;
    SHAPE ABUTMENT ;
    PORT
      LAYER metal3 ;
      RECT 0.000 42.874 0.038 42.931 ;
    END
  END rd_out[54]
  PIN rd_out[55]
    DIRECTION OUTPUT ;
    USE SIGNAL ;
    SHAPE ABUTMENT ;
    PORT
      LAYER metal3 ;
      RECT 0.000 43.102 0.038 43.159 ;
    END
  END rd_out[55]
  PIN rd_out[56]
    DIRECTION OUTPUT ;
    USE SIGNAL ;
    SHAPE ABUTMENT ;
    PORT
      LAYER metal3 ;
      RECT 0.000 43.330 0.038 43.387 ;
    END
  END rd_out[56]
  PIN rd_out[57]
    DIRECTION OUTPUT ;
    USE SIGNAL ;
    SHAPE ABUTMENT ;
    PORT
      LAYER metal3 ;
      RECT 0.000 43.558 0.038 43.615 ;
    END
  END rd_out[57]
  PIN rd_out[58]
    DIRECTION OUTPUT ;
    USE SIGNAL ;
    SHAPE ABUTMENT ;
    PORT
      LAYER metal3 ;
      RECT 0.000 43.787 0.038 43.843 ;
    END
  END rd_out[58]
  PIN rd_out[59]
    DIRECTION OUTPUT ;
    USE SIGNAL ;
    SHAPE ABUTMENT ;
    PORT
      LAYER metal3 ;
      RECT 0.000 44.015 0.038 44.071 ;
    END
  END rd_out[59]
  PIN rd_out[60]
    DIRECTION OUTPUT ;
    USE SIGNAL ;
    SHAPE ABUTMENT ;
    PORT
      LAYER metal3 ;
      RECT 0.000 44.243 0.038 44.299 ;
    END
  END rd_out[60]
  PIN rd_out[61]
    DIRECTION OUTPUT ;
    USE SIGNAL ;
    SHAPE ABUTMENT ;
    PORT
      LAYER metal3 ;
      RECT 0.000 44.471 0.038 44.527 ;
    END
  END rd_out[61]
  PIN rd_out[62]
    DIRECTION OUTPUT ;
    USE SIGNAL ;
    SHAPE ABUTMENT ;
    PORT
      LAYER metal3 ;
      RECT 0.000 44.699 0.038 44.755 ;
    END
  END rd_out[62]
  PIN rd_out[63]
    DIRECTION OUTPUT ;
    USE SIGNAL ;
    SHAPE ABUTMENT ;
    PORT
      LAYER metal3 ;
      RECT 0.000 44.927 0.038 44.984 ;
    END
  END rd_out[63]
  PIN rd_out[64]
    DIRECTION OUTPUT ;
    USE SIGNAL ;
    SHAPE ABUTMENT ;
    PORT
      LAYER metal3 ;
      RECT 0.000 45.154 0.038 45.212 ;
    END
  END rd_out[64]
  PIN rd_out[65]
    DIRECTION OUTPUT ;
    USE SIGNAL ;
    SHAPE ABUTMENT ;
    PORT
      LAYER metal3 ;
      RECT 0.000 45.382 0.038 45.440 ;
    END
  END rd_out[65]
  PIN rd_out[66]
    DIRECTION OUTPUT ;
    USE SIGNAL ;
    SHAPE ABUTMENT ;
    PORT
      LAYER metal3 ;
      RECT 0.000 45.610 0.038 45.668 ;
    END
  END rd_out[66]
  PIN rd_out[67]
    DIRECTION OUTPUT ;
    USE SIGNAL ;
    SHAPE ABUTMENT ;
    PORT
      LAYER metal3 ;
      RECT 0.000 45.838 0.038 45.896 ;
    END
  END rd_out[67]
  PIN rd_out[68]
    DIRECTION OUTPUT ;
    USE SIGNAL ;
    SHAPE ABUTMENT ;
    PORT
      LAYER metal3 ;
      RECT 0.000 46.067 0.038 46.124 ;
    END
  END rd_out[68]
  PIN rd_out[69]
    DIRECTION OUTPUT ;
    USE SIGNAL ;
    SHAPE ABUTMENT ;
    PORT
      LAYER metal3 ;
      RECT 0.000 46.295 0.038 46.352 ;
    END
  END rd_out[69]
  PIN rd_out[70]
    DIRECTION OUTPUT ;
    USE SIGNAL ;
    SHAPE ABUTMENT ;
    PORT
      LAYER metal3 ;
      RECT 0.000 46.523 0.038 46.580 ;
    END
  END rd_out[70]
  PIN rd_out[71]
    DIRECTION OUTPUT ;
    USE SIGNAL ;
    SHAPE ABUTMENT ;
    PORT
      LAYER metal3 ;
      RECT 0.000 46.751 0.038 46.808 ;
    END
  END rd_out[71]
  PIN rd_out[72]
    DIRECTION OUTPUT ;
    USE SIGNAL ;
    SHAPE ABUTMENT ;
    PORT
      LAYER metal3 ;
      RECT 0.000 46.979 0.038 47.036 ;
    END
  END rd_out[72]
  PIN rd_out[73]
    DIRECTION OUTPUT ;
    USE SIGNAL ;
    SHAPE ABUTMENT ;
    PORT
      LAYER metal3 ;
      RECT 0.000 47.207 0.038 47.264 ;
    END
  END rd_out[73]
  PIN rd_out[74]
    DIRECTION OUTPUT ;
    USE SIGNAL ;
    SHAPE ABUTMENT ;
    PORT
      LAYER metal3 ;
      RECT 0.000 47.435 0.038 47.492 ;
    END
  END rd_out[74]
  PIN rd_out[75]
    DIRECTION OUTPUT ;
    USE SIGNAL ;
    SHAPE ABUTMENT ;
    PORT
      LAYER metal3 ;
      RECT 0.000 47.663 0.038 47.720 ;
    END
  END rd_out[75]
  PIN rd_out[76]
    DIRECTION OUTPUT ;
    USE SIGNAL ;
    SHAPE ABUTMENT ;
    PORT
      LAYER metal3 ;
      RECT 0.000 47.891 0.038 47.948 ;
    END
  END rd_out[76]
  PIN rd_out[77]
    DIRECTION OUTPUT ;
    USE SIGNAL ;
    SHAPE ABUTMENT ;
    PORT
      LAYER metal3 ;
      RECT 0.000 48.120 0.038 48.176 ;
    END
  END rd_out[77]
  PIN rd_out[78]
    DIRECTION OUTPUT ;
    USE SIGNAL ;
    SHAPE ABUTMENT ;
    PORT
      LAYER metal3 ;
      RECT 0.000 48.348 0.038 48.404 ;
    END
  END rd_out[78]
  PIN rd_out[79]
    DIRECTION OUTPUT ;
    USE SIGNAL ;
    SHAPE ABUTMENT ;
    PORT
      LAYER metal3 ;
      RECT 0.000 48.576 0.038 48.632 ;
    END
  END rd_out[79]
  PIN rd_out[80]
    DIRECTION OUTPUT ;
    USE SIGNAL ;
    SHAPE ABUTMENT ;
    PORT
      LAYER metal3 ;
      RECT 0.000 48.804 0.038 48.860 ;
    END
  END rd_out[80]
  PIN rd_out[81]
    DIRECTION OUTPUT ;
    USE SIGNAL ;
    SHAPE ABUTMENT ;
    PORT
      LAYER metal3 ;
      RECT 0.000 49.032 0.038 49.089 ;
    END
  END rd_out[81]
  PIN rd_out[82]
    DIRECTION OUTPUT ;
    USE SIGNAL ;
    SHAPE ABUTMENT ;
    PORT
      LAYER metal3 ;
      RECT 0.000 49.260 0.038 49.317 ;
    END
  END rd_out[82]
  PIN rd_out[83]
    DIRECTION OUTPUT ;
    USE SIGNAL ;
    SHAPE ABUTMENT ;
    PORT
      LAYER metal3 ;
      RECT 0.000 49.487 0.038 49.545 ;
    END
  END rd_out[83]
  PIN rd_out[84]
    DIRECTION OUTPUT ;
    USE SIGNAL ;
    SHAPE ABUTMENT ;
    PORT
      LAYER metal3 ;
      RECT 0.000 49.715 0.038 49.773 ;
    END
  END rd_out[84]
  PIN rd_out[85]
    DIRECTION OUTPUT ;
    USE SIGNAL ;
    SHAPE ABUTMENT ;
    PORT
      LAYER metal3 ;
      RECT 0.000 49.943 0.038 50.001 ;
    END
  END rd_out[85]
  PIN rd_out[86]
    DIRECTION OUTPUT ;
    USE SIGNAL ;
    SHAPE ABUTMENT ;
    PORT
      LAYER metal3 ;
      RECT 0.000 50.172 0.038 50.229 ;
    END
  END rd_out[86]
  PIN rd_out[87]
    DIRECTION OUTPUT ;
    USE SIGNAL ;
    SHAPE ABUTMENT ;
    PORT
      LAYER metal3 ;
      RECT 0.000 50.400 0.038 50.457 ;
    END
  END rd_out[87]
  PIN rd_out[88]
    DIRECTION OUTPUT ;
    USE SIGNAL ;
    SHAPE ABUTMENT ;
    PORT
      LAYER metal3 ;
      RECT 0.000 50.628 0.038 50.685 ;
    END
  END rd_out[88]
  PIN rd_out[89]
    DIRECTION OUTPUT ;
    USE SIGNAL ;
    SHAPE ABUTMENT ;
    PORT
      LAYER metal3 ;
      RECT 0.000 50.856 0.038 50.913 ;
    END
  END rd_out[89]
  PIN rd_out[90]
    DIRECTION OUTPUT ;
    USE SIGNAL ;
    SHAPE ABUTMENT ;
    PORT
      LAYER metal3 ;
      RECT 0.000 51.084 0.038 51.141 ;
    END
  END rd_out[90]
  PIN rd_out[91]
    DIRECTION OUTPUT ;
    USE SIGNAL ;
    SHAPE ABUTMENT ;
    PORT
      LAYER metal3 ;
      RECT 0.000 51.312 0.038 51.369 ;
    END
  END rd_out[91]
  PIN rd_out[92]
    DIRECTION OUTPUT ;
    USE SIGNAL ;
    SHAPE ABUTMENT ;
    PORT
      LAYER metal3 ;
      RECT 0.000 51.540 0.038 51.597 ;
    END
  END rd_out[92]
  PIN rd_out[93]
    DIRECTION OUTPUT ;
    USE SIGNAL ;
    SHAPE ABUTMENT ;
    PORT
      LAYER metal3 ;
      RECT 0.000 51.768 0.038 51.825 ;
    END
  END rd_out[93]
  PIN rd_out[94]
    DIRECTION OUTPUT ;
    USE SIGNAL ;
    SHAPE ABUTMENT ;
    PORT
      LAYER metal3 ;
      RECT 0.000 51.996 0.038 52.053 ;
    END
  END rd_out[94]
  PIN rd_out[95]
    DIRECTION OUTPUT ;
    USE SIGNAL ;
    SHAPE ABUTMENT ;
    PORT
      LAYER metal3 ;
      RECT 0.000 52.224 0.038 52.281 ;
    END
  END rd_out[95]
  PIN rd_out[96]
    DIRECTION OUTPUT ;
    USE SIGNAL ;
    SHAPE ABUTMENT ;
    PORT
      LAYER metal3 ;
      RECT 0.000 52.453 0.038 52.509 ;
    END
  END rd_out[96]
  PIN rd_out[97]
    DIRECTION OUTPUT ;
    USE SIGNAL ;
    SHAPE ABUTMENT ;
    PORT
      LAYER metal3 ;
      RECT 0.000 52.681 0.038 52.737 ;
    END
  END rd_out[97]
  PIN rd_out[98]
    DIRECTION OUTPUT ;
    USE SIGNAL ;
    SHAPE ABUTMENT ;
    PORT
      LAYER metal3 ;
      RECT 0.000 52.909 0.038 52.965 ;
    END
  END rd_out[98]
  PIN rd_out[99]
    DIRECTION OUTPUT ;
    USE SIGNAL ;
    SHAPE ABUTMENT ;
    PORT
      LAYER metal3 ;
      RECT 0.000 53.137 0.038 53.193 ;
    END
  END rd_out[99]
  PIN rd_out[100]
    DIRECTION OUTPUT ;
    USE SIGNAL ;
    SHAPE ABUTMENT ;
    PORT
      LAYER metal3 ;
      RECT 0.000 53.365 0.038 53.422 ;
    END
  END rd_out[100]
  PIN rd_out[101]
    DIRECTION OUTPUT ;
    USE SIGNAL ;
    SHAPE ABUTMENT ;
    PORT
      LAYER metal3 ;
      RECT 0.000 53.592 0.038 53.650 ;
    END
  END rd_out[101]
  PIN rd_out[102]
    DIRECTION OUTPUT ;
    USE SIGNAL ;
    SHAPE ABUTMENT ;
    PORT
      LAYER metal3 ;
      RECT 0.000 53.820 0.038 53.878 ;
    END
  END rd_out[102]
  PIN rd_out[103]
    DIRECTION OUTPUT ;
    USE SIGNAL ;
    SHAPE ABUTMENT ;
    PORT
      LAYER metal3 ;
      RECT 0.000 54.048 0.038 54.106 ;
    END
  END rd_out[103]
  PIN rd_out[104]
    DIRECTION OUTPUT ;
    USE SIGNAL ;
    SHAPE ABUTMENT ;
    PORT
      LAYER metal3 ;
      RECT 0.000 54.276 0.038 54.334 ;
    END
  END rd_out[104]
  PIN rd_out[105]
    DIRECTION OUTPUT ;
    USE SIGNAL ;
    SHAPE ABUTMENT ;
    PORT
      LAYER metal3 ;
      RECT 0.000 54.505 0.038 54.562 ;
    END
  END rd_out[105]
  PIN rd_out[106]
    DIRECTION OUTPUT ;
    USE SIGNAL ;
    SHAPE ABUTMENT ;
    PORT
      LAYER metal3 ;
      RECT 0.000 54.733 0.038 54.790 ;
    END
  END rd_out[106]
  PIN rd_out[107]
    DIRECTION OUTPUT ;
    USE SIGNAL ;
    SHAPE ABUTMENT ;
    PORT
      LAYER metal3 ;
      RECT 0.000 54.961 0.038 55.018 ;
    END
  END rd_out[107]
  PIN rd_out[108]
    DIRECTION OUTPUT ;
    USE SIGNAL ;
    SHAPE ABUTMENT ;
    PORT
      LAYER metal3 ;
      RECT 0.000 55.189 0.038 55.246 ;
    END
  END rd_out[108]
  PIN rd_out[109]
    DIRECTION OUTPUT ;
    USE SIGNAL ;
    SHAPE ABUTMENT ;
    PORT
      LAYER metal3 ;
      RECT 0.000 55.417 0.038 55.474 ;
    END
  END rd_out[109]
  PIN rd_out[110]
    DIRECTION OUTPUT ;
    USE SIGNAL ;
    SHAPE ABUTMENT ;
    PORT
      LAYER metal3 ;
      RECT 0.000 55.645 0.038 55.702 ;
    END
  END rd_out[110]
  PIN rd_out[111]
    DIRECTION OUTPUT ;
    USE SIGNAL ;
    SHAPE ABUTMENT ;
    PORT
      LAYER metal3 ;
      RECT 0.000 55.873 0.038 55.930 ;
    END
  END rd_out[111]
  PIN rd_out[112]
    DIRECTION OUTPUT ;
    USE SIGNAL ;
    SHAPE ABUTMENT ;
    PORT
      LAYER metal3 ;
      RECT 0.000 56.101 0.038 56.158 ;
    END
  END rd_out[112]
  PIN rd_out[113]
    DIRECTION OUTPUT ;
    USE SIGNAL ;
    SHAPE ABUTMENT ;
    PORT
      LAYER metal3 ;
      RECT 0.000 56.329 0.038 56.386 ;
    END
  END rd_out[113]
  PIN rd_out[114]
    DIRECTION OUTPUT ;
    USE SIGNAL ;
    SHAPE ABUTMENT ;
    PORT
      LAYER metal3 ;
      RECT 0.000 56.558 0.038 56.614 ;
    END
  END rd_out[114]
  PIN rd_out[115]
    DIRECTION OUTPUT ;
    USE SIGNAL ;
    SHAPE ABUTMENT ;
    PORT
      LAYER metal3 ;
      RECT 0.000 56.786 0.038 56.842 ;
    END
  END rd_out[115]
  PIN rd_out[116]
    DIRECTION OUTPUT ;
    USE SIGNAL ;
    SHAPE ABUTMENT ;
    PORT
      LAYER metal3 ;
      RECT 0.000 57.014 0.038 57.070 ;
    END
  END rd_out[116]
  PIN rd_out[117]
    DIRECTION OUTPUT ;
    USE SIGNAL ;
    SHAPE ABUTMENT ;
    PORT
      LAYER metal3 ;
      RECT 0.000 57.242 0.038 57.298 ;
    END
  END rd_out[117]
  PIN rd_out[118]
    DIRECTION OUTPUT ;
    USE SIGNAL ;
    SHAPE ABUTMENT ;
    PORT
      LAYER metal3 ;
      RECT 0.000 57.470 0.038 57.526 ;
    END
  END rd_out[118]
  PIN rd_out[119]
    DIRECTION OUTPUT ;
    USE SIGNAL ;
    SHAPE ABUTMENT ;
    PORT
      LAYER metal3 ;
      RECT 0.000 57.698 0.038 57.755 ;
    END
  END rd_out[119]
  PIN rd_out[120]
    DIRECTION OUTPUT ;
    USE SIGNAL ;
    SHAPE ABUTMENT ;
    PORT
      LAYER metal3 ;
      RECT 0.000 57.925 0.038 57.983 ;
    END
  END rd_out[120]
  PIN rd_out[121]
    DIRECTION OUTPUT ;
    USE SIGNAL ;
    SHAPE ABUTMENT ;
    PORT
      LAYER metal3 ;
      RECT 0.000 58.153 0.038 58.211 ;
    END
  END rd_out[121]
  PIN rd_out[122]
    DIRECTION OUTPUT ;
    USE SIGNAL ;
    SHAPE ABUTMENT ;
    PORT
      LAYER metal3 ;
      RECT 0.000 58.381 0.038 58.439 ;
    END
  END rd_out[122]
  PIN rd_out[123]
    DIRECTION OUTPUT ;
    USE SIGNAL ;
    SHAPE ABUTMENT ;
    PORT
      LAYER metal3 ;
      RECT 0.000 58.609 0.038 58.667 ;
    END
  END rd_out[123]
  PIN wd_in[0]
    DIRECTION INPUT ;
    USE SIGNAL ;
    SHAPE ABUTMENT ;
    PORT
      LAYER metal3 ;
      RECT 0.000 58.838 0.038 58.895 ;
    END
  END wd_in[0]
  PIN wd_in[1]
    DIRECTION INPUT ;
    USE SIGNAL ;
    SHAPE ABUTMENT ;
    PORT
      LAYER metal3 ;
      RECT 0.000 59.066 0.038 59.123 ;
    END
  END wd_in[1]
  PIN wd_in[2]
    DIRECTION INPUT ;
    USE SIGNAL ;
    SHAPE ABUTMENT ;
    PORT
      LAYER metal3 ;
      RECT 0.000 59.294 0.038 59.351 ;
    END
  END wd_in[2]
  PIN wd_in[3]
    DIRECTION INPUT ;
    USE SIGNAL ;
    SHAPE ABUTMENT ;
    PORT
      LAYER metal3 ;
      RECT 0.000 59.522 0.038 59.579 ;
    END
  END wd_in[3]
  PIN wd_in[4]
    DIRECTION INPUT ;
    USE SIGNAL ;
    SHAPE ABUTMENT ;
    PORT
      LAYER metal3 ;
      RECT 0.000 59.750 0.038 59.807 ;
    END
  END wd_in[4]
  PIN wd_in[5]
    DIRECTION INPUT ;
    USE SIGNAL ;
    SHAPE ABUTMENT ;
    PORT
      LAYER metal3 ;
      RECT 0.000 59.978 0.038 60.035 ;
    END
  END wd_in[5]
  PIN wd_in[6]
    DIRECTION INPUT ;
    USE SIGNAL ;
    SHAPE ABUTMENT ;
    PORT
      LAYER metal3 ;
      RECT 0.000 60.206 0.038 60.263 ;
    END
  END wd_in[6]
  PIN wd_in[7]
    DIRECTION INPUT ;
    USE SIGNAL ;
    SHAPE ABUTMENT ;
    PORT
      LAYER metal3 ;
      RECT 0.000 60.434 0.038 60.491 ;
    END
  END wd_in[7]
  PIN wd_in[8]
    DIRECTION INPUT ;
    USE SIGNAL ;
    SHAPE ABUTMENT ;
    PORT
      LAYER metal3 ;
      RECT 0.000 60.662 0.038 60.719 ;
    END
  END wd_in[8]
  PIN wd_in[9]
    DIRECTION INPUT ;
    USE SIGNAL ;
    SHAPE ABUTMENT ;
    PORT
      LAYER metal3 ;
      RECT 0.000 60.891 0.038 60.947 ;
    END
  END wd_in[9]
  PIN wd_in[10]
    DIRECTION INPUT ;
    USE SIGNAL ;
    SHAPE ABUTMENT ;
    PORT
      LAYER metal3 ;
      RECT 0.000 61.119 0.038 61.175 ;
    END
  END wd_in[10]
  PIN wd_in[11]
    DIRECTION INPUT ;
    USE SIGNAL ;
    SHAPE ABUTMENT ;
    PORT
      LAYER metal3 ;
      RECT 0.000 61.347 0.038 61.403 ;
    END
  END wd_in[11]
  PIN wd_in[12]
    DIRECTION INPUT ;
    USE SIGNAL ;
    SHAPE ABUTMENT ;
    PORT
      LAYER metal3 ;
      RECT 0.000 61.575 0.038 61.631 ;
    END
  END wd_in[12]
  PIN wd_in[13]
    DIRECTION INPUT ;
    USE SIGNAL ;
    SHAPE ABUTMENT ;
    PORT
      LAYER metal3 ;
      RECT 0.000 61.803 0.038 61.860 ;
    END
  END wd_in[13]
  PIN wd_in[14]
    DIRECTION INPUT ;
    USE SIGNAL ;
    SHAPE ABUTMENT ;
    PORT
      LAYER metal3 ;
      RECT 0.000 62.031 0.038 62.088 ;
    END
  END wd_in[14]
  PIN wd_in[15]
    DIRECTION INPUT ;
    USE SIGNAL ;
    SHAPE ABUTMENT ;
    PORT
      LAYER metal3 ;
      RECT 0.000 62.258 0.038 62.316 ;
    END
  END wd_in[15]
  PIN wd_in[16]
    DIRECTION INPUT ;
    USE SIGNAL ;
    SHAPE ABUTMENT ;
    PORT
      LAYER metal3 ;
      RECT 0.000 62.486 0.038 62.544 ;
    END
  END wd_in[16]
  PIN wd_in[17]
    DIRECTION INPUT ;
    USE SIGNAL ;
    SHAPE ABUTMENT ;
    PORT
      LAYER metal3 ;
      RECT 0.000 62.714 0.038 62.772 ;
    END
  END wd_in[17]
  PIN wd_in[18]
    DIRECTION INPUT ;
    USE SIGNAL ;
    SHAPE ABUTMENT ;
    PORT
      LAYER metal3 ;
      RECT 0.000 62.943 0.038 63.000 ;
    END
  END wd_in[18]
  PIN wd_in[19]
    DIRECTION INPUT ;
    USE SIGNAL ;
    SHAPE ABUTMENT ;
    PORT
      LAYER metal3 ;
      RECT 0.000 63.171 0.038 63.228 ;
    END
  END wd_in[19]
  PIN wd_in[20]
    DIRECTION INPUT ;
    USE SIGNAL ;
    SHAPE ABUTMENT ;
    PORT
      LAYER metal3 ;
      RECT 0.000 63.399 0.038 63.456 ;
    END
  END wd_in[20]
  PIN wd_in[21]
    DIRECTION INPUT ;
    USE SIGNAL ;
    SHAPE ABUTMENT ;
    PORT
      LAYER metal3 ;
      RECT 0.000 63.627 0.038 63.684 ;
    END
  END wd_in[21]
  PIN wd_in[22]
    DIRECTION INPUT ;
    USE SIGNAL ;
    SHAPE ABUTMENT ;
    PORT
      LAYER metal3 ;
      RECT 0.000 63.855 0.038 63.912 ;
    END
  END wd_in[22]
  PIN wd_in[23]
    DIRECTION INPUT ;
    USE SIGNAL ;
    SHAPE ABUTMENT ;
    PORT
      LAYER metal3 ;
      RECT 0.000 64.083 0.038 64.140 ;
    END
  END wd_in[23]
  PIN wd_in[24]
    DIRECTION INPUT ;
    USE SIGNAL ;
    SHAPE ABUTMENT ;
    PORT
      LAYER metal3 ;
      RECT 0.000 64.311 0.038 64.368 ;
    END
  END wd_in[24]
  PIN wd_in[25]
    DIRECTION INPUT ;
    USE SIGNAL ;
    SHAPE ABUTMENT ;
    PORT
      LAYER metal3 ;
      RECT 0.000 64.539 0.038 64.596 ;
    END
  END wd_in[25]
  PIN wd_in[26]
    DIRECTION INPUT ;
    USE SIGNAL ;
    SHAPE ABUTMENT ;
    PORT
      LAYER metal3 ;
      RECT 0.000 64.767 0.038 64.824 ;
    END
  END wd_in[26]
  PIN wd_in[27]
    DIRECTION INPUT ;
    USE SIGNAL ;
    SHAPE ABUTMENT ;
    PORT
      LAYER metal3 ;
      RECT 0.000 64.995 0.038 65.052 ;
    END
  END wd_in[27]
  PIN wd_in[28]
    DIRECTION INPUT ;
    USE SIGNAL ;
    SHAPE ABUTMENT ;
    PORT
      LAYER metal3 ;
      RECT 0.000 65.224 0.038 65.280 ;
    END
  END wd_in[28]
  PIN wd_in[29]
    DIRECTION INPUT ;
    USE SIGNAL ;
    SHAPE ABUTMENT ;
    PORT
      LAYER metal3 ;
      RECT 0.000 65.452 0.038 65.508 ;
    END
  END wd_in[29]
  PIN wd_in[30]
    DIRECTION INPUT ;
    USE SIGNAL ;
    SHAPE ABUTMENT ;
    PORT
      LAYER metal3 ;
      RECT 0.000 65.680 0.038 65.736 ;
    END
  END wd_in[30]
  PIN wd_in[31]
    DIRECTION INPUT ;
    USE SIGNAL ;
    SHAPE ABUTMENT ;
    PORT
      LAYER metal3 ;
      RECT 0.000 65.908 0.038 65.964 ;
    END
  END wd_in[31]
  PIN wd_in[32]
    DIRECTION INPUT ;
    USE SIGNAL ;
    SHAPE ABUTMENT ;
    PORT
      LAYER metal3 ;
      RECT 0.000 66.136 0.038 66.193 ;
    END
  END wd_in[32]
  PIN wd_in[33]
    DIRECTION INPUT ;
    USE SIGNAL ;
    SHAPE ABUTMENT ;
    PORT
      LAYER metal3 ;
      RECT 0.000 66.364 0.038 66.421 ;
    END
  END wd_in[33]
  PIN wd_in[34]
    DIRECTION INPUT ;
    USE SIGNAL ;
    SHAPE ABUTMENT ;
    PORT
      LAYER metal3 ;
      RECT 0.000 66.591 0.038 66.649 ;
    END
  END wd_in[34]
  PIN wd_in[35]
    DIRECTION INPUT ;
    USE SIGNAL ;
    SHAPE ABUTMENT ;
    PORT
      LAYER metal3 ;
      RECT 0.000 66.819 0.038 66.877 ;
    END
  END wd_in[35]
  PIN wd_in[36]
    DIRECTION INPUT ;
    USE SIGNAL ;
    SHAPE ABUTMENT ;
    PORT
      LAYER metal3 ;
      RECT 0.000 67.047 0.038 67.105 ;
    END
  END wd_in[36]
  PIN wd_in[37]
    DIRECTION INPUT ;
    USE SIGNAL ;
    SHAPE ABUTMENT ;
    PORT
      LAYER metal3 ;
      RECT 0.000 67.276 0.038 67.333 ;
    END
  END wd_in[37]
  PIN wd_in[38]
    DIRECTION INPUT ;
    USE SIGNAL ;
    SHAPE ABUTMENT ;
    PORT
      LAYER metal3 ;
      RECT 0.000 67.504 0.038 67.561 ;
    END
  END wd_in[38]
  PIN wd_in[39]
    DIRECTION INPUT ;
    USE SIGNAL ;
    SHAPE ABUTMENT ;
    PORT
      LAYER metal3 ;
      RECT 0.000 67.732 0.038 67.789 ;
    END
  END wd_in[39]
  PIN wd_in[40]
    DIRECTION INPUT ;
    USE SIGNAL ;
    SHAPE ABUTMENT ;
    PORT
      LAYER metal3 ;
      RECT 0.000 67.960 0.038 68.017 ;
    END
  END wd_in[40]
  PIN wd_in[41]
    DIRECTION INPUT ;
    USE SIGNAL ;
    SHAPE ABUTMENT ;
    PORT
      LAYER metal3 ;
      RECT 0.000 68.188 0.038 68.245 ;
    END
  END wd_in[41]
  PIN wd_in[42]
    DIRECTION INPUT ;
    USE SIGNAL ;
    SHAPE ABUTMENT ;
    PORT
      LAYER metal3 ;
      RECT 0.000 68.416 0.038 68.473 ;
    END
  END wd_in[42]
  PIN wd_in[43]
    DIRECTION INPUT ;
    USE SIGNAL ;
    SHAPE ABUTMENT ;
    PORT
      LAYER metal3 ;
      RECT 0.000 68.644 0.038 68.701 ;
    END
  END wd_in[43]
  PIN wd_in[44]
    DIRECTION INPUT ;
    USE SIGNAL ;
    SHAPE ABUTMENT ;
    PORT
      LAYER metal3 ;
      RECT 0.000 68.872 0.038 68.929 ;
    END
  END wd_in[44]
  PIN wd_in[45]
    DIRECTION INPUT ;
    USE SIGNAL ;
    SHAPE ABUTMENT ;
    PORT
      LAYER metal3 ;
      RECT 0.000 69.100 0.038 69.157 ;
    END
  END wd_in[45]
  PIN wd_in[46]
    DIRECTION INPUT ;
    USE SIGNAL ;
    SHAPE ABUTMENT ;
    PORT
      LAYER metal3 ;
      RECT 0.000 69.329 0.038 69.385 ;
    END
  END wd_in[46]
  PIN wd_in[47]
    DIRECTION INPUT ;
    USE SIGNAL ;
    SHAPE ABUTMENT ;
    PORT
      LAYER metal3 ;
      RECT 0.000 69.557 0.038 69.613 ;
    END
  END wd_in[47]
  PIN wd_in[48]
    DIRECTION INPUT ;
    USE SIGNAL ;
    SHAPE ABUTMENT ;
    PORT
      LAYER metal3 ;
      RECT 0.000 69.785 0.038 69.841 ;
    END
  END wd_in[48]
  PIN wd_in[49]
    DIRECTION INPUT ;
    USE SIGNAL ;
    SHAPE ABUTMENT ;
    PORT
      LAYER metal3 ;
      RECT 0.000 70.013 0.038 70.069 ;
    END
  END wd_in[49]
  PIN wd_in[50]
    DIRECTION INPUT ;
    USE SIGNAL ;
    SHAPE ABUTMENT ;
    PORT
      LAYER metal3 ;
      RECT 0.000 70.241 0.038 70.297 ;
    END
  END wd_in[50]
  PIN wd_in[51]
    DIRECTION INPUT ;
    USE SIGNAL ;
    SHAPE ABUTMENT ;
    PORT
      LAYER metal3 ;
      RECT 0.000 70.469 0.038 70.526 ;
    END
  END wd_in[51]
  PIN wd_in[52]
    DIRECTION INPUT ;
    USE SIGNAL ;
    SHAPE ABUTMENT ;
    PORT
      LAYER metal3 ;
      RECT 0.000 70.697 0.038 70.754 ;
    END
  END wd_in[52]
  PIN wd_in[53]
    DIRECTION INPUT ;
    USE SIGNAL ;
    SHAPE ABUTMENT ;
    PORT
      LAYER metal3 ;
      RECT 0.000 70.924 0.038 70.982 ;
    END
  END wd_in[53]
  PIN wd_in[54]
    DIRECTION INPUT ;
    USE SIGNAL ;
    SHAPE ABUTMENT ;
    PORT
      LAYER metal3 ;
      RECT 0.000 71.152 0.038 71.210 ;
    END
  END wd_in[54]
  PIN wd_in[55]
    DIRECTION INPUT ;
    USE SIGNAL ;
    SHAPE ABUTMENT ;
    PORT
      LAYER metal3 ;
      RECT 0.000 71.380 0.038 71.438 ;
    END
  END wd_in[55]
  PIN wd_in[56]
    DIRECTION INPUT ;
    USE SIGNAL ;
    SHAPE ABUTMENT ;
    PORT
      LAYER metal3 ;
      RECT 0.000 71.609 0.038 71.666 ;
    END
  END wd_in[56]
  PIN wd_in[57]
    DIRECTION INPUT ;
    USE SIGNAL ;
    SHAPE ABUTMENT ;
    PORT
      LAYER metal3 ;
      RECT 0.000 71.837 0.038 71.894 ;
    END
  END wd_in[57]
  PIN wd_in[58]
    DIRECTION INPUT ;
    USE SIGNAL ;
    SHAPE ABUTMENT ;
    PORT
      LAYER metal3 ;
      RECT 0.000 72.065 0.038 72.122 ;
    END
  END wd_in[58]
  PIN wd_in[59]
    DIRECTION INPUT ;
    USE SIGNAL ;
    SHAPE ABUTMENT ;
    PORT
      LAYER metal3 ;
      RECT 0.000 72.293 0.038 72.350 ;
    END
  END wd_in[59]
  PIN wd_in[60]
    DIRECTION INPUT ;
    USE SIGNAL ;
    SHAPE ABUTMENT ;
    PORT
      LAYER metal3 ;
      RECT 0.000 72.521 0.038 72.578 ;
    END
  END wd_in[60]
  PIN wd_in[61]
    DIRECTION INPUT ;
    USE SIGNAL ;
    SHAPE ABUTMENT ;
    PORT
      LAYER metal3 ;
      RECT 0.000 72.749 0.038 72.806 ;
    END
  END wd_in[61]
  PIN wd_in[62]
    DIRECTION INPUT ;
    USE SIGNAL ;
    SHAPE ABUTMENT ;
    PORT
      LAYER metal3 ;
      RECT 0.000 72.977 0.038 73.034 ;
    END
  END wd_in[62]
  PIN wd_in[63]
    DIRECTION INPUT ;
    USE SIGNAL ;
    SHAPE ABUTMENT ;
    PORT
      LAYER metal3 ;
      RECT 0.000 73.205 0.038 73.262 ;
    END
  END wd_in[63]
  PIN wd_in[64]
    DIRECTION INPUT ;
    USE SIGNAL ;
    SHAPE ABUTMENT ;
    PORT
      LAYER metal3 ;
      RECT 0.000 73.433 0.038 73.490 ;
    END
  END wd_in[64]
  PIN wd_in[65]
    DIRECTION INPUT ;
    USE SIGNAL ;
    SHAPE ABUTMENT ;
    PORT
      LAYER metal3 ;
      RECT 0.000 73.662 0.038 73.718 ;
    END
  END wd_in[65]
  PIN wd_in[66]
    DIRECTION INPUT ;
    USE SIGNAL ;
    SHAPE ABUTMENT ;
    PORT
      LAYER metal3 ;
      RECT 0.000 73.890 0.038 73.946 ;
    END
  END wd_in[66]
  PIN wd_in[67]
    DIRECTION INPUT ;
    USE SIGNAL ;
    SHAPE ABUTMENT ;
    PORT
      LAYER metal3 ;
      RECT 0.000 74.118 0.038 74.174 ;
    END
  END wd_in[67]
  PIN wd_in[68]
    DIRECTION INPUT ;
    USE SIGNAL ;
    SHAPE ABUTMENT ;
    PORT
      LAYER metal3 ;
      RECT 0.000 74.346 0.038 74.402 ;
    END
  END wd_in[68]
  PIN wd_in[69]
    DIRECTION INPUT ;
    USE SIGNAL ;
    SHAPE ABUTMENT ;
    PORT
      LAYER metal3 ;
      RECT 0.000 74.574 0.038 74.630 ;
    END
  END wd_in[69]
  PIN wd_in[70]
    DIRECTION INPUT ;
    USE SIGNAL ;
    SHAPE ABUTMENT ;
    PORT
      LAYER metal3 ;
      RECT 0.000 74.802 0.038 74.859 ;
    END
  END wd_in[70]
  PIN wd_in[71]
    DIRECTION INPUT ;
    USE SIGNAL ;
    SHAPE ABUTMENT ;
    PORT
      LAYER metal3 ;
      RECT 0.000 75.029 0.038 75.087 ;
    END
  END wd_in[71]
  PIN wd_in[72]
    DIRECTION INPUT ;
    USE SIGNAL ;
    SHAPE ABUTMENT ;
    PORT
      LAYER metal3 ;
      RECT 0.000 75.257 0.038 75.315 ;
    END
  END wd_in[72]
  PIN wd_in[73]
    DIRECTION INPUT ;
    USE SIGNAL ;
    SHAPE ABUTMENT ;
    PORT
      LAYER metal3 ;
      RECT 0.000 75.485 0.038 75.543 ;
    END
  END wd_in[73]
  PIN wd_in[74]
    DIRECTION INPUT ;
    USE SIGNAL ;
    SHAPE ABUTMENT ;
    PORT
      LAYER metal3 ;
      RECT 0.000 75.714 0.038 75.771 ;
    END
  END wd_in[74]
  PIN wd_in[75]
    DIRECTION INPUT ;
    USE SIGNAL ;
    SHAPE ABUTMENT ;
    PORT
      LAYER metal3 ;
      RECT 0.000 75.942 0.038 75.999 ;
    END
  END wd_in[75]
  PIN wd_in[76]
    DIRECTION INPUT ;
    USE SIGNAL ;
    SHAPE ABUTMENT ;
    PORT
      LAYER metal3 ;
      RECT 0.000 76.170 0.038 76.227 ;
    END
  END wd_in[76]
  PIN wd_in[77]
    DIRECTION INPUT ;
    USE SIGNAL ;
    SHAPE ABUTMENT ;
    PORT
      LAYER metal3 ;
      RECT 0.000 76.398 0.038 76.455 ;
    END
  END wd_in[77]
  PIN wd_in[78]
    DIRECTION INPUT ;
    USE SIGNAL ;
    SHAPE ABUTMENT ;
    PORT
      LAYER metal3 ;
      RECT 0.000 76.626 0.038 76.683 ;
    END
  END wd_in[78]
  PIN wd_in[79]
    DIRECTION INPUT ;
    USE SIGNAL ;
    SHAPE ABUTMENT ;
    PORT
      LAYER metal3 ;
      RECT 0.000 76.854 0.038 76.911 ;
    END
  END wd_in[79]
  PIN wd_in[80]
    DIRECTION INPUT ;
    USE SIGNAL ;
    SHAPE ABUTMENT ;
    PORT
      LAYER metal3 ;
      RECT 0.000 77.082 0.038 77.139 ;
    END
  END wd_in[80]
  PIN wd_in[81]
    DIRECTION INPUT ;
    USE SIGNAL ;
    SHAPE ABUTMENT ;
    PORT
      LAYER metal3 ;
      RECT 0.000 77.310 0.038 77.367 ;
    END
  END wd_in[81]
  PIN wd_in[82]
    DIRECTION INPUT ;
    USE SIGNAL ;
    SHAPE ABUTMENT ;
    PORT
      LAYER metal3 ;
      RECT 0.000 77.538 0.038 77.595 ;
    END
  END wd_in[82]
  PIN wd_in[83]
    DIRECTION INPUT ;
    USE SIGNAL ;
    SHAPE ABUTMENT ;
    PORT
      LAYER metal3 ;
      RECT 0.000 77.766 0.038 77.823 ;
    END
  END wd_in[83]
  PIN wd_in[84]
    DIRECTION INPUT ;
    USE SIGNAL ;
    SHAPE ABUTMENT ;
    PORT
      LAYER metal3 ;
      RECT 0.000 77.995 0.038 78.051 ;
    END
  END wd_in[84]
  PIN wd_in[85]
    DIRECTION INPUT ;
    USE SIGNAL ;
    SHAPE ABUTMENT ;
    PORT
      LAYER metal3 ;
      RECT 0.000 78.223 0.038 78.279 ;
    END
  END wd_in[85]
  PIN wd_in[86]
    DIRECTION INPUT ;
    USE SIGNAL ;
    SHAPE ABUTMENT ;
    PORT
      LAYER metal3 ;
      RECT 0.000 78.451 0.038 78.507 ;
    END
  END wd_in[86]
  PIN wd_in[87]
    DIRECTION INPUT ;
    USE SIGNAL ;
    SHAPE ABUTMENT ;
    PORT
      LAYER metal3 ;
      RECT 0.000 78.679 0.038 78.735 ;
    END
  END wd_in[87]
  PIN wd_in[88]
    DIRECTION INPUT ;
    USE SIGNAL ;
    SHAPE ABUTMENT ;
    PORT
      LAYER metal3 ;
      RECT 0.000 78.907 0.038 78.964 ;
    END
  END wd_in[88]
  PIN wd_in[89]
    DIRECTION INPUT ;
    USE SIGNAL ;
    SHAPE ABUTMENT ;
    PORT
      LAYER metal3 ;
      RECT 0.000 79.135 0.038 79.192 ;
    END
  END wd_in[89]
  PIN wd_in[90]
    DIRECTION INPUT ;
    USE SIGNAL ;
    SHAPE ABUTMENT ;
    PORT
      LAYER metal3 ;
      RECT 0.000 79.362 0.038 79.420 ;
    END
  END wd_in[90]
  PIN wd_in[91]
    DIRECTION INPUT ;
    USE SIGNAL ;
    SHAPE ABUTMENT ;
    PORT
      LAYER metal3 ;
      RECT 0.000 79.590 0.038 79.648 ;
    END
  END wd_in[91]
  PIN wd_in[92]
    DIRECTION INPUT ;
    USE SIGNAL ;
    SHAPE ABUTMENT ;
    PORT
      LAYER metal3 ;
      RECT 0.000 79.818 0.038 79.876 ;
    END
  END wd_in[92]
  PIN wd_in[93]
    DIRECTION INPUT ;
    USE SIGNAL ;
    SHAPE ABUTMENT ;
    PORT
      LAYER metal3 ;
      RECT 0.000 80.047 0.038 80.104 ;
    END
  END wd_in[93]
  PIN wd_in[94]
    DIRECTION INPUT ;
    USE SIGNAL ;
    SHAPE ABUTMENT ;
    PORT
      LAYER metal3 ;
      RECT 0.000 80.275 0.038 80.332 ;
    END
  END wd_in[94]
  PIN wd_in[95]
    DIRECTION INPUT ;
    USE SIGNAL ;
    SHAPE ABUTMENT ;
    PORT
      LAYER metal3 ;
      RECT 0.000 80.503 0.038 80.560 ;
    END
  END wd_in[95]
  PIN wd_in[96]
    DIRECTION INPUT ;
    USE SIGNAL ;
    SHAPE ABUTMENT ;
    PORT
      LAYER metal3 ;
      RECT 0.000 80.731 0.038 80.788 ;
    END
  END wd_in[96]
  PIN wd_in[97]
    DIRECTION INPUT ;
    USE SIGNAL ;
    SHAPE ABUTMENT ;
    PORT
      LAYER metal3 ;
      RECT 0.000 80.959 0.038 81.016 ;
    END
  END wd_in[97]
  PIN wd_in[98]
    DIRECTION INPUT ;
    USE SIGNAL ;
    SHAPE ABUTMENT ;
    PORT
      LAYER metal3 ;
      RECT 0.000 81.187 0.038 81.244 ;
    END
  END wd_in[98]
  PIN wd_in[99]
    DIRECTION INPUT ;
    USE SIGNAL ;
    SHAPE ABUTMENT ;
    PORT
      LAYER metal3 ;
      RECT 0.000 81.415 0.038 81.472 ;
    END
  END wd_in[99]
  PIN wd_in[100]
    DIRECTION INPUT ;
    USE SIGNAL ;
    SHAPE ABUTMENT ;
    PORT
      LAYER metal3 ;
      RECT 0.000 81.643 0.038 81.700 ;
    END
  END wd_in[100]
  PIN wd_in[101]
    DIRECTION INPUT ;
    USE SIGNAL ;
    SHAPE ABUTMENT ;
    PORT
      LAYER metal3 ;
      RECT 0.000 81.871 0.038 81.928 ;
    END
  END wd_in[101]
  PIN wd_in[102]
    DIRECTION INPUT ;
    USE SIGNAL ;
    SHAPE ABUTMENT ;
    PORT
      LAYER metal3 ;
      RECT 0.000 82.099 0.038 82.156 ;
    END
  END wd_in[102]
  PIN wd_in[103]
    DIRECTION INPUT ;
    USE SIGNAL ;
    SHAPE ABUTMENT ;
    PORT
      LAYER metal3 ;
      RECT 0.000 82.328 0.038 82.384 ;
    END
  END wd_in[103]
  PIN wd_in[104]
    DIRECTION INPUT ;
    USE SIGNAL ;
    SHAPE ABUTMENT ;
    PORT
      LAYER metal3 ;
      RECT 0.000 82.556 0.038 82.612 ;
    END
  END wd_in[104]
  PIN wd_in[105]
    DIRECTION INPUT ;
    USE SIGNAL ;
    SHAPE ABUTMENT ;
    PORT
      LAYER metal3 ;
      RECT 0.000 82.784 0.038 82.840 ;
    END
  END wd_in[105]
  PIN wd_in[106]
    DIRECTION INPUT ;
    USE SIGNAL ;
    SHAPE ABUTMENT ;
    PORT
      LAYER metal3 ;
      RECT 0.000 83.012 0.038 83.068 ;
    END
  END wd_in[106]
  PIN wd_in[107]
    DIRECTION INPUT ;
    USE SIGNAL ;
    SHAPE ABUTMENT ;
    PORT
      LAYER metal3 ;
      RECT 0.000 83.240 0.038 83.297 ;
    END
  END wd_in[107]
  PIN wd_in[108]
    DIRECTION INPUT ;
    USE SIGNAL ;
    SHAPE ABUTMENT ;
    PORT
      LAYER metal3 ;
      RECT 0.000 83.468 0.038 83.525 ;
    END
  END wd_in[108]
  PIN wd_in[109]
    DIRECTION INPUT ;
    USE SIGNAL ;
    SHAPE ABUTMENT ;
    PORT
      LAYER metal3 ;
      RECT 0.000 83.695 0.038 83.753 ;
    END
  END wd_in[109]
  PIN wd_in[110]
    DIRECTION INPUT ;
    USE SIGNAL ;
    SHAPE ABUTMENT ;
    PORT
      LAYER metal3 ;
      RECT 0.000 83.923 0.038 83.981 ;
    END
  END wd_in[110]
  PIN wd_in[111]
    DIRECTION INPUT ;
    USE SIGNAL ;
    SHAPE ABUTMENT ;
    PORT
      LAYER metal3 ;
      RECT 0.000 84.151 0.038 84.209 ;
    END
  END wd_in[111]
  PIN wd_in[112]
    DIRECTION INPUT ;
    USE SIGNAL ;
    SHAPE ABUTMENT ;
    PORT
      LAYER metal3 ;
      RECT 0.000 84.380 0.038 84.437 ;
    END
  END wd_in[112]
  PIN wd_in[113]
    DIRECTION INPUT ;
    USE SIGNAL ;
    SHAPE ABUTMENT ;
    PORT
      LAYER metal3 ;
      RECT 0.000 84.608 0.038 84.665 ;
    END
  END wd_in[113]
  PIN wd_in[114]
    DIRECTION INPUT ;
    USE SIGNAL ;
    SHAPE ABUTMENT ;
    PORT
      LAYER metal3 ;
      RECT 0.000 84.836 0.038 84.893 ;
    END
  END wd_in[114]
  PIN wd_in[115]
    DIRECTION INPUT ;
    USE SIGNAL ;
    SHAPE ABUTMENT ;
    PORT
      LAYER metal3 ;
      RECT 0.000 85.064 0.038 85.121 ;
    END
  END wd_in[115]
  PIN wd_in[116]
    DIRECTION INPUT ;
    USE SIGNAL ;
    SHAPE ABUTMENT ;
    PORT
      LAYER metal3 ;
      RECT 0.000 85.292 0.038 85.349 ;
    END
  END wd_in[116]
  PIN wd_in[117]
    DIRECTION INPUT ;
    USE SIGNAL ;
    SHAPE ABUTMENT ;
    PORT
      LAYER metal3 ;
      RECT 0.000 85.520 0.038 85.577 ;
    END
  END wd_in[117]
  PIN wd_in[118]
    DIRECTION INPUT ;
    USE SIGNAL ;
    SHAPE ABUTMENT ;
    PORT
      LAYER metal3 ;
      RECT 0.000 85.748 0.038 85.805 ;
    END
  END wd_in[118]
  PIN wd_in[119]
    DIRECTION INPUT ;
    USE SIGNAL ;
    SHAPE ABUTMENT ;
    PORT
      LAYER metal3 ;
      RECT 0.000 85.976 0.038 86.033 ;
    END
  END wd_in[119]
  PIN wd_in[120]
    DIRECTION INPUT ;
    USE SIGNAL ;
    SHAPE ABUTMENT ;
    PORT
      LAYER metal3 ;
      RECT 0.000 86.204 0.038 86.261 ;
    END
  END wd_in[120]
  PIN wd_in[121]
    DIRECTION INPUT ;
    USE SIGNAL ;
    SHAPE ABUTMENT ;
    PORT
      LAYER metal3 ;
      RECT 0.000 86.433 0.038 86.489 ;
    END
  END wd_in[121]
  PIN wd_in[122]
    DIRECTION INPUT ;
    USE SIGNAL ;
    SHAPE ABUTMENT ;
    PORT
      LAYER metal3 ;
      RECT 0.000 86.661 0.038 86.717 ;
    END
  END wd_in[122]
  PIN wd_in[123]
    DIRECTION INPUT ;
    USE SIGNAL ;
    SHAPE ABUTMENT ;
    PORT
      LAYER metal3 ;
      RECT 0.000 86.889 0.038 86.945 ;
    END
  END wd_in[123]
  PIN addr_in[0]
    DIRECTION INPUT ;
    USE SIGNAL ;
    SHAPE ABUTMENT ;
    PORT
      LAYER metal3 ;
      RECT 0.000 87.117 0.038 87.173 ;
    END
  END addr_in[0]
  PIN addr_in[1]
    DIRECTION INPUT ;
    USE SIGNAL ;
    SHAPE ABUTMENT ;
    PORT
      LAYER metal3 ;
      RECT 0.000 87.345 0.038 87.401 ;
    END
  END addr_in[1]
  PIN addr_in[2]
    DIRECTION INPUT ;
    USE SIGNAL ;
    SHAPE ABUTMENT ;
    PORT
      LAYER metal3 ;
      RECT 0.000 87.573 0.038 87.630 ;
    END
  END addr_in[2]
  PIN addr_in[3]
    DIRECTION INPUT ;
    USE SIGNAL ;
    SHAPE ABUTMENT ;
    PORT
      LAYER metal3 ;
      RECT 0.000 87.801 0.038 87.858 ;
    END
  END addr_in[3]
  PIN addr_in[4]
    DIRECTION INPUT ;
    USE SIGNAL ;
    SHAPE ABUTMENT ;
    PORT
      LAYER metal3 ;
      RECT 0.000 88.028 0.038 88.086 ;
    END
  END addr_in[4]
  PIN addr_in[5]
    DIRECTION INPUT ;
    USE SIGNAL ;
    SHAPE ABUTMENT ;
    PORT
      LAYER metal3 ;
      RECT 0.000 88.256 0.038 88.314 ;
    END
  END addr_in[5]
  PIN we_in
    DIRECTION INPUT ;
    USE SIGNAL ;
    SHAPE ABUTMENT ;
    PORT
      LAYER metal3 ;
      RECT 0.000 88.484 0.038 88.542 ;
    END
  END we_in
  PIN ce_in
    DIRECTION INPUT ;
    USE SIGNAL ;
    SHAPE ABUTMENT ;
    PORT
      LAYER metal3 ;
      RECT 0.000 88.713 0.038 88.770 ;
    END
  END ce_in
  PIN clk
    DIRECTION INPUT ;
    USE SIGNAL ;
    SHAPE ABUTMENT ;
    PORT
      LAYER metal3 ;
      RECT 0.000 88.941 0.038 88.998 ;
    END
  END clk
  PIN VSS
    DIRECTION INOUT ;
    USE GROUND ;
    PORT
      LAYER metal4 ;
      RECT 1.451 2.280 1.604 89.430 ;
      RECT 3.895 2.280 4.048 89.430 ;
      RECT 6.339 2.280 6.492 89.430 ;
      RECT 8.783 2.280 8.935 89.430 ;
      RECT 11.227 2.280 11.380 89.430 ;
      RECT 13.671 2.280 13.824 89.430 ;
      RECT 16.114 2.280 16.267 89.430 ;
      RECT 18.559 2.280 18.711 89.430 ;
      RECT 21.003 2.280 21.155 89.430 ;
      RECT 23.446 2.280 23.599 89.430 ;
      RECT 25.890 2.280 26.043 89.430 ;
      RECT 28.334 2.280 28.487 89.430 ;
      RECT 30.778 2.280 30.931 89.430 ;
      RECT 33.222 2.280 33.375 89.430 ;
      RECT 35.666 2.280 35.819 89.430 ;
      RECT 38.110 2.280 38.263 89.430 ;
      RECT 40.554 2.280 40.706 89.430 ;
    END
  END VSS
  PIN VDD
    DIRECTION INOUT ;
    USE POWER ;
    PORT
      LAYER metal4 ;
      RECT 2.673 2.280 2.826 89.430 ;
      RECT 5.117 2.280 5.270 89.430 ;
      RECT 7.561 2.280 7.713 89.430 ;
      RECT 10.005 2.280 10.158 89.430 ;
      RECT 12.449 2.280 12.602 89.430 ;
      RECT 14.892 2.280 15.046 89.430 ;
      RECT 17.337 2.280 17.489 89.430 ;
      RECT 19.781 2.280 19.933 89.430 ;
      RECT 22.225 2.280 22.377 89.430 ;
      RECT 24.668 2.280 24.821 89.430 ;
      RECT 27.112 2.280 27.265 89.430 ;
      RECT 29.556 2.280 29.709 89.430 ;
      RECT 32.000 2.280 32.153 89.430 ;
      RECT 34.444 2.280 34.597 89.430 ;
      RECT 36.888 2.280 37.041 89.430 ;
      RECT 39.332 2.280 39.485 89.430 ;
    END
  END VDD
  OBS
    LAYER metal1 ;
    RECT 0.000 0.000 42.599 91.710 ;
    LAYER metal2 ;
    RECT 0.000 0.000 42.599 91.710 ;
    LAYER metal3 ;
    RECT 0.038 0.000 42.599 91.710 ;
    RECT 0.000 0.000 0.038 2.280 ;
    RECT 0.000 2.338 0.038 2.508 ;
    RECT 0.000 2.566 0.038 2.736 ;
    RECT 0.000 2.794 0.038 2.964 ;
    RECT 0.000 3.022 0.038 3.192 ;
    RECT 0.000 3.250 0.038 3.421 ;
    RECT 0.000 3.478 0.038 3.649 ;
    RECT 0.000 3.706 0.038 3.877 ;
    RECT 0.000 3.934 0.038 4.105 ;
    RECT 0.000 4.162 0.038 4.333 ;
    RECT 0.000 4.390 0.038 4.561 ;
    RECT 0.000 4.618 0.038 4.789 ;
    RECT 0.000 4.846 0.038 5.017 ;
    RECT 0.000 5.074 0.038 5.245 ;
    RECT 0.000 5.302 0.038 5.474 ;
    RECT 0.000 5.530 0.038 5.702 ;
    RECT 0.000 5.758 0.038 5.930 ;
    RECT 0.000 5.986 0.038 6.158 ;
    RECT 0.000 6.214 0.038 6.386 ;
    RECT 0.000 6.443 0.038 6.613 ;
    RECT 0.000 6.671 0.038 6.841 ;
    RECT 0.000 6.899 0.038 7.069 ;
    RECT 0.000 7.127 0.038 7.297 ;
    RECT 0.000 7.355 0.038 7.526 ;
    RECT 0.000 7.583 0.038 7.754 ;
    RECT 0.000 7.811 0.038 7.982 ;
    RECT 0.000 8.039 0.038 8.210 ;
    RECT 0.000 8.267 0.038 8.438 ;
    RECT 0.000 8.495 0.038 8.666 ;
    RECT 0.000 8.723 0.038 8.894 ;
    RECT 0.000 8.951 0.038 9.122 ;
    RECT 0.000 9.179 0.038 9.350 ;
    RECT 0.000 9.407 0.038 9.578 ;
    RECT 0.000 9.635 0.038 9.807 ;
    RECT 0.000 9.863 0.038 10.035 ;
    RECT 0.000 10.091 0.038 10.263 ;
    RECT 0.000 10.319 0.038 10.491 ;
    RECT 0.000 10.547 0.038 10.718 ;
    RECT 0.000 10.776 0.038 10.946 ;
    RECT 0.000 11.004 0.038 11.174 ;
    RECT 0.000 11.232 0.038 11.402 ;
    RECT 0.000 11.460 0.038 11.630 ;
    RECT 0.000 11.688 0.038 11.859 ;
    RECT 0.000 11.916 0.038 12.087 ;
    RECT 0.000 12.144 0.038 12.315 ;
    RECT 0.000 12.372 0.038 12.543 ;
    RECT 0.000 12.600 0.038 12.771 ;
    RECT 0.000 12.828 0.038 12.999 ;
    RECT 0.000 13.056 0.038 13.227 ;
    RECT 0.000 13.284 0.038 13.455 ;
    RECT 0.000 13.512 0.038 13.683 ;
    RECT 0.000 13.740 0.038 13.912 ;
    RECT 0.000 13.968 0.038 14.140 ;
    RECT 0.000 14.196 0.038 14.368 ;
    RECT 0.000 14.424 0.038 14.596 ;
    RECT 0.000 14.652 0.038 14.824 ;
    RECT 0.000 14.880 0.038 15.051 ;
    RECT 0.000 15.109 0.038 15.279 ;
    RECT 0.000 15.337 0.038 15.507 ;
    RECT 0.000 15.565 0.038 15.735 ;
    RECT 0.000 15.793 0.038 15.963 ;
    RECT 0.000 16.021 0.038 16.192 ;
    RECT 0.000 16.249 0.038 16.420 ;
    RECT 0.000 16.477 0.038 16.648 ;
    RECT 0.000 16.705 0.038 16.876 ;
    RECT 0.000 16.933 0.038 17.104 ;
    RECT 0.000 17.161 0.038 17.332 ;
    RECT 0.000 17.389 0.038 17.560 ;
    RECT 0.000 17.617 0.038 17.788 ;
    RECT 0.000 17.845 0.038 18.016 ;
    RECT 0.000 18.073 0.038 18.245 ;
    RECT 0.000 18.301 0.038 18.473 ;
    RECT 0.000 18.529 0.038 18.701 ;
    RECT 0.000 18.757 0.038 18.929 ;
    RECT 0.000 18.985 0.038 19.157 ;
    RECT 0.000 19.214 0.038 19.384 ;
    RECT 0.000 19.442 0.038 19.612 ;
    RECT 0.000 19.670 0.038 19.840 ;
    RECT 0.000 19.898 0.038 20.068 ;
    RECT 0.000 20.126 0.038 20.297 ;
    RECT 0.000 20.354 0.038 20.525 ;
    RECT 0.000 20.582 0.038 20.753 ;
    RECT 0.000 20.810 0.038 20.981 ;
    RECT 0.000 21.038 0.038 21.209 ;
    RECT 0.000 21.266 0.038 21.437 ;
    RECT 0.000 21.494 0.038 21.665 ;
    RECT 0.000 21.722 0.038 21.893 ;
    RECT 0.000 21.950 0.038 22.121 ;
    RECT 0.000 22.178 0.038 22.349 ;
    RECT 0.000 22.406 0.038 22.578 ;
    RECT 0.000 22.634 0.038 22.806 ;
    RECT 0.000 22.862 0.038 23.034 ;
    RECT 0.000 23.090 0.038 23.262 ;
    RECT 0.000 23.318 0.038 23.490 ;
    RECT 0.000 23.547 0.038 23.717 ;
    RECT 0.000 23.775 0.038 23.945 ;
    RECT 0.000 24.003 0.038 24.173 ;
    RECT 0.000 24.231 0.038 24.401 ;
    RECT 0.000 24.459 0.038 24.630 ;
    RECT 0.000 24.687 0.038 24.858 ;
    RECT 0.000 24.915 0.038 25.086 ;
    RECT 0.000 25.143 0.038 25.314 ;
    RECT 0.000 25.371 0.038 25.542 ;
    RECT 0.000 25.599 0.038 25.770 ;
    RECT 0.000 25.827 0.038 25.998 ;
    RECT 0.000 26.055 0.038 26.226 ;
    RECT 0.000 26.283 0.038 26.454 ;
    RECT 0.000 26.511 0.038 26.683 ;
    RECT 0.000 26.739 0.038 26.911 ;
    RECT 0.000 26.967 0.038 27.139 ;
    RECT 0.000 27.195 0.038 27.367 ;
    RECT 0.000 27.423 0.038 27.595 ;
    RECT 0.000 27.651 0.038 27.823 ;
    RECT 0.000 27.880 0.038 28.050 ;
    RECT 0.000 28.108 0.038 28.278 ;
    RECT 0.000 28.336 0.038 28.506 ;
    RECT 0.000 28.564 0.038 28.734 ;
    RECT 0.000 28.792 0.038 28.963 ;
    RECT 0.000 29.020 0.038 29.191 ;
    RECT 0.000 29.248 0.038 29.419 ;
    RECT 0.000 29.476 0.038 29.647 ;
    RECT 0.000 29.704 0.038 29.875 ;
    RECT 0.000 29.932 0.038 30.103 ;
    RECT 0.000 30.160 0.038 30.331 ;
    RECT 0.000 30.388 0.038 30.559 ;
    RECT 0.000 30.616 0.038 30.787 ;
    RECT 0.000 30.844 0.038 31.016 ;
    RECT 0.000 31.072 0.038 31.244 ;
    RECT 0.000 31.300 0.038 31.472 ;
    RECT 0.000 31.528 0.038 31.700 ;
    RECT 0.000 31.756 0.038 31.928 ;
    RECT 0.000 31.984 0.038 32.155 ;
    RECT 0.000 32.213 0.038 32.383 ;
    RECT 0.000 32.441 0.038 32.611 ;
    RECT 0.000 32.669 0.038 32.839 ;
    RECT 0.000 32.897 0.038 33.068 ;
    RECT 0.000 33.125 0.038 33.296 ;
    RECT 0.000 33.353 0.038 33.524 ;
    RECT 0.000 33.581 0.038 33.752 ;
    RECT 0.000 33.809 0.038 33.980 ;
    RECT 0.000 34.037 0.038 34.208 ;
    RECT 0.000 34.265 0.038 34.436 ;
    RECT 0.000 34.493 0.038 34.664 ;
    RECT 0.000 34.721 0.038 34.892 ;
    RECT 0.000 34.949 0.038 35.120 ;
    RECT 0.000 35.177 0.038 35.349 ;
    RECT 0.000 35.405 0.038 35.577 ;
    RECT 0.000 35.633 0.038 35.805 ;
    RECT 0.000 35.861 0.038 36.033 ;
    RECT 0.000 36.089 0.038 36.261 ;
    RECT 0.000 36.318 0.038 36.488 ;
    RECT 0.000 36.546 0.038 36.716 ;
    RECT 0.000 36.774 0.038 36.944 ;
    RECT 0.000 37.002 0.038 37.172 ;
    RECT 0.000 37.230 0.038 37.401 ;
    RECT 0.000 37.458 0.038 37.629 ;
    RECT 0.000 37.686 0.038 37.857 ;
    RECT 0.000 37.914 0.038 38.085 ;
    RECT 0.000 38.142 0.038 38.313 ;
    RECT 0.000 38.370 0.038 38.541 ;
    RECT 0.000 38.598 0.038 38.769 ;
    RECT 0.000 38.826 0.038 38.997 ;
    RECT 0.000 39.054 0.038 39.225 ;
    RECT 0.000 39.282 0.038 39.454 ;
    RECT 0.000 39.510 0.038 39.682 ;
    RECT 0.000 39.738 0.038 39.910 ;
    RECT 0.000 39.966 0.038 40.138 ;
    RECT 0.000 40.194 0.038 40.366 ;
    RECT 0.000 40.422 0.038 40.594 ;
    RECT 0.000 40.651 0.038 40.821 ;
    RECT 0.000 40.879 0.038 41.049 ;
    RECT 0.000 41.107 0.038 41.277 ;
    RECT 0.000 41.335 0.038 41.505 ;
    RECT 0.000 41.563 0.038 41.734 ;
    RECT 0.000 41.791 0.038 41.962 ;
    RECT 0.000 42.019 0.038 42.190 ;
    RECT 0.000 42.247 0.038 42.418 ;
    RECT 0.000 42.475 0.038 42.646 ;
    RECT 0.000 42.703 0.038 42.874 ;
    RECT 0.000 42.931 0.038 43.102 ;
    RECT 0.000 43.159 0.038 43.330 ;
    RECT 0.000 43.387 0.038 43.558 ;
    RECT 0.000 43.615 0.038 43.787 ;
    RECT 0.000 43.843 0.038 44.015 ;
    RECT 0.000 44.071 0.038 44.243 ;
    RECT 0.000 44.299 0.038 44.471 ;
    RECT 0.000 44.527 0.038 44.699 ;
    RECT 0.000 44.755 0.038 44.927 ;
    RECT 0.000 44.984 0.038 45.154 ;
    RECT 0.000 45.212 0.038 45.382 ;
    RECT 0.000 45.440 0.038 45.610 ;
    RECT 0.000 45.668 0.038 45.838 ;
    RECT 0.000 45.896 0.038 46.067 ;
    RECT 0.000 46.124 0.038 46.295 ;
    RECT 0.000 46.352 0.038 46.523 ;
    RECT 0.000 46.580 0.038 46.751 ;
    RECT 0.000 46.808 0.038 46.979 ;
    RECT 0.000 47.036 0.038 47.207 ;
    RECT 0.000 47.264 0.038 47.435 ;
    RECT 0.000 47.492 0.038 47.663 ;
    RECT 0.000 47.720 0.038 47.891 ;
    RECT 0.000 47.948 0.038 48.120 ;
    RECT 0.000 48.176 0.038 48.348 ;
    RECT 0.000 48.404 0.038 48.576 ;
    RECT 0.000 48.632 0.038 48.804 ;
    RECT 0.000 48.860 0.038 49.032 ;
    RECT 0.000 49.089 0.038 49.260 ;
    RECT 0.000 49.317 0.038 49.487 ;
    RECT 0.000 49.545 0.038 49.715 ;
    RECT 0.000 49.773 0.038 49.943 ;
    RECT 0.000 50.001 0.038 50.172 ;
    RECT 0.000 50.229 0.038 50.400 ;
    RECT 0.000 50.457 0.038 50.628 ;
    RECT 0.000 50.685 0.038 50.856 ;
    RECT 0.000 50.913 0.038 51.084 ;
    RECT 0.000 51.141 0.038 51.312 ;
    RECT 0.000 51.369 0.038 51.540 ;
    RECT 0.000 51.597 0.038 51.768 ;
    RECT 0.000 51.825 0.038 51.996 ;
    RECT 0.000 52.053 0.038 52.224 ;
    RECT 0.000 52.281 0.038 52.453 ;
    RECT 0.000 52.509 0.038 52.681 ;
    RECT 0.000 52.737 0.038 52.909 ;
    RECT 0.000 52.965 0.038 53.137 ;
    RECT 0.000 53.193 0.038 53.365 ;
    RECT 0.000 53.422 0.038 53.592 ;
    RECT 0.000 53.650 0.038 53.820 ;
    RECT 0.000 53.878 0.038 54.048 ;
    RECT 0.000 54.106 0.038 54.276 ;
    RECT 0.000 54.334 0.038 54.505 ;
    RECT 0.000 54.562 0.038 54.733 ;
    RECT 0.000 54.790 0.038 54.961 ;
    RECT 0.000 55.018 0.038 55.189 ;
    RECT 0.000 55.246 0.038 55.417 ;
    RECT 0.000 55.474 0.038 55.645 ;
    RECT 0.000 55.702 0.038 55.873 ;
    RECT 0.000 55.930 0.038 56.101 ;
    RECT 0.000 56.158 0.038 56.329 ;
    RECT 0.000 56.386 0.038 56.558 ;
    RECT 0.000 56.614 0.038 56.786 ;
    RECT 0.000 56.842 0.038 57.014 ;
    RECT 0.000 57.070 0.038 57.242 ;
    RECT 0.000 57.298 0.038 57.470 ;
    RECT 0.000 57.526 0.038 57.698 ;
    RECT 0.000 57.755 0.038 57.925 ;
    RECT 0.000 57.983 0.038 58.153 ;
    RECT 0.000 58.211 0.038 58.381 ;
    RECT 0.000 58.439 0.038 58.609 ;
    RECT 0.000 58.667 0.038 58.838 ;
    RECT 0.000 58.895 0.038 59.066 ;
    RECT 0.000 59.123 0.038 59.294 ;
    RECT 0.000 59.351 0.038 59.522 ;
    RECT 0.000 59.579 0.038 59.750 ;
    RECT 0.000 59.807 0.038 59.978 ;
    RECT 0.000 60.035 0.038 60.206 ;
    RECT 0.000 60.263 0.038 60.434 ;
    RECT 0.000 60.491 0.038 60.662 ;
    RECT 0.000 60.719 0.038 60.891 ;
    RECT 0.000 60.947 0.038 61.119 ;
    RECT 0.000 61.175 0.038 61.347 ;
    RECT 0.000 61.403 0.038 61.575 ;
    RECT 0.000 61.631 0.038 61.803 ;
    RECT 0.000 61.860 0.038 62.031 ;
    RECT 0.000 62.088 0.038 62.258 ;
    RECT 0.000 62.316 0.038 62.486 ;
    RECT 0.000 62.544 0.038 62.714 ;
    RECT 0.000 62.772 0.038 62.943 ;
    RECT 0.000 63.000 0.038 63.171 ;
    RECT 0.000 63.228 0.038 63.399 ;
    RECT 0.000 63.456 0.038 63.627 ;
    RECT 0.000 63.684 0.038 63.855 ;
    RECT 0.000 63.912 0.038 64.083 ;
    RECT 0.000 64.140 0.038 64.311 ;
    RECT 0.000 64.368 0.038 64.539 ;
    RECT 0.000 64.596 0.038 64.767 ;
    RECT 0.000 64.824 0.038 64.995 ;
    RECT 0.000 65.052 0.038 65.224 ;
    RECT 0.000 65.280 0.038 65.452 ;
    RECT 0.000 65.508 0.038 65.680 ;
    RECT 0.000 65.736 0.038 65.908 ;
    RECT 0.000 65.964 0.038 66.136 ;
    RECT 0.000 66.193 0.038 66.364 ;
    RECT 0.000 66.421 0.038 66.591 ;
    RECT 0.000 66.649 0.038 66.819 ;
    RECT 0.000 66.877 0.038 67.047 ;
    RECT 0.000 67.105 0.038 67.276 ;
    RECT 0.000 67.333 0.038 67.504 ;
    RECT 0.000 67.561 0.038 67.732 ;
    RECT 0.000 67.789 0.038 67.960 ;
    RECT 0.000 68.017 0.038 68.188 ;
    RECT 0.000 68.245 0.038 68.416 ;
    RECT 0.000 68.473 0.038 68.644 ;
    RECT 0.000 68.701 0.038 68.872 ;
    RECT 0.000 68.929 0.038 69.100 ;
    RECT 0.000 69.157 0.038 69.329 ;
    RECT 0.000 69.385 0.038 69.557 ;
    RECT 0.000 69.613 0.038 69.785 ;
    RECT 0.000 69.841 0.038 70.013 ;
    RECT 0.000 70.069 0.038 70.241 ;
    RECT 0.000 70.297 0.038 70.469 ;
    RECT 0.000 70.526 0.038 70.697 ;
    RECT 0.000 70.754 0.038 70.924 ;
    RECT 0.000 70.982 0.038 71.152 ;
    RECT 0.000 71.210 0.038 71.380 ;
    RECT 0.000 71.438 0.038 71.609 ;
    RECT 0.000 71.666 0.038 71.837 ;
    RECT 0.000 71.894 0.038 72.065 ;
    RECT 0.000 72.122 0.038 72.293 ;
    RECT 0.000 72.350 0.038 72.521 ;
    RECT 0.000 72.578 0.038 72.749 ;
    RECT 0.000 72.806 0.038 72.977 ;
    RECT 0.000 73.034 0.038 73.205 ;
    RECT 0.000 73.262 0.038 73.433 ;
    RECT 0.000 73.490 0.038 73.662 ;
    RECT 0.000 73.718 0.038 73.890 ;
    RECT 0.000 73.946 0.038 74.118 ;
    RECT 0.000 74.174 0.038 74.346 ;
    RECT 0.000 74.402 0.038 74.574 ;
    RECT 0.000 74.630 0.038 74.802 ;
    RECT 0.000 74.859 0.038 75.029 ;
    RECT 0.000 75.087 0.038 75.257 ;
    RECT 0.000 75.315 0.038 75.485 ;
    RECT 0.000 75.543 0.038 75.714 ;
    RECT 0.000 75.771 0.038 75.942 ;
    RECT 0.000 75.999 0.038 76.170 ;
    RECT 0.000 76.227 0.038 76.398 ;
    RECT 0.000 76.455 0.038 76.626 ;
    RECT 0.000 76.683 0.038 76.854 ;
    RECT 0.000 76.911 0.038 77.082 ;
    RECT 0.000 77.139 0.038 77.310 ;
    RECT 0.000 77.367 0.038 77.538 ;
    RECT 0.000 77.595 0.038 77.766 ;
    RECT 0.000 77.823 0.038 77.995 ;
    RECT 0.000 78.051 0.038 78.223 ;
    RECT 0.000 78.279 0.038 78.451 ;
    RECT 0.000 78.507 0.038 78.679 ;
    RECT 0.000 78.735 0.038 78.907 ;
    RECT 0.000 78.964 0.038 79.135 ;
    RECT 0.000 79.192 0.038 79.362 ;
    RECT 0.000 79.420 0.038 79.590 ;
    RECT 0.000 79.648 0.038 79.818 ;
    RECT 0.000 79.876 0.038 80.047 ;
    RECT 0.000 80.104 0.038 80.275 ;
    RECT 0.000 80.332 0.038 80.503 ;
    RECT 0.000 80.560 0.038 80.731 ;
    RECT 0.000 80.788 0.038 80.959 ;
    RECT 0.000 81.016 0.038 81.187 ;
    RECT 0.000 81.244 0.038 81.415 ;
    RECT 0.000 81.472 0.038 81.643 ;
    RECT 0.000 81.700 0.038 81.871 ;
    RECT 0.000 81.928 0.038 82.099 ;
    RECT 0.000 82.156 0.038 82.328 ;
    RECT 0.000 82.384 0.038 82.556 ;
    RECT 0.000 82.612 0.038 82.784 ;
    RECT 0.000 82.840 0.038 83.012 ;
    RECT 0.000 83.068 0.038 83.240 ;
    RECT 0.000 83.297 0.038 83.468 ;
    RECT 0.000 83.525 0.038 83.695 ;
    RECT 0.000 83.753 0.038 83.923 ;
    RECT 0.000 83.981 0.038 84.151 ;
    RECT 0.000 84.209 0.038 84.380 ;
    RECT 0.000 84.437 0.038 84.608 ;
    RECT 0.000 84.665 0.038 84.836 ;
    RECT 0.000 84.893 0.038 85.064 ;
    RECT 0.000 85.121 0.038 85.292 ;
    RECT 0.000 85.349 0.038 85.520 ;
    RECT 0.000 85.577 0.038 85.748 ;
    RECT 0.000 85.805 0.038 85.976 ;
    RECT 0.000 86.033 0.038 86.204 ;
    RECT 0.000 86.261 0.038 86.433 ;
    RECT 0.000 86.489 0.038 86.661 ;
    RECT 0.000 86.717 0.038 86.889 ;
    RECT 0.000 86.945 0.038 87.117 ;
    RECT 0.000 87.173 0.038 87.345 ;
    RECT 0.000 87.401 0.038 87.573 ;
    RECT 0.000 87.630 0.038 87.801 ;
    RECT 0.000 87.858 0.038 88.028 ;
    RECT 0.000 88.086 0.038 88.256 ;
    RECT 0.000 88.314 0.038 88.484 ;
    RECT 0.000 88.542 0.038 88.713 ;
    RECT 0.000 88.770 0.038 88.941 ;
    RECT 0.000 88.998 0.038 91.710 ;
    LAYER metal4 ;
    RECT 0.000 0.000 42.599 2.280 ;
    RECT 0.000 89.430 42.599 91.710 ;
    RECT 0.000 2.280 1.451 89.430 ;
    RECT 1.604 2.280 2.673 89.430 ;
    RECT 2.826 2.280 3.895 89.430 ;
    RECT 4.048 2.280 5.117 89.430 ;
    RECT 5.270 2.280 6.339 89.430 ;
    RECT 6.492 2.280 7.561 89.430 ;
    RECT 7.713 2.280 8.783 89.430 ;
    RECT 8.935 2.280 10.005 89.430 ;
    RECT 10.158 2.280 11.227 89.430 ;
    RECT 11.380 2.280 12.449 89.430 ;
    RECT 12.602 2.280 13.671 89.430 ;
    RECT 13.824 2.280 14.892 89.430 ;
    RECT 15.046 2.280 16.114 89.430 ;
    RECT 16.267 2.280 17.337 89.430 ;
    RECT 17.489 2.280 18.559 89.430 ;
    RECT 18.711 2.280 19.781 89.430 ;
    RECT 19.933 2.280 21.003 89.430 ;
    RECT 21.155 2.280 22.225 89.430 ;
    RECT 22.377 2.280 23.446 89.430 ;
    RECT 23.599 2.280 24.668 89.430 ;
    RECT 24.821 2.280 25.890 89.430 ;
    RECT 26.043 2.280 27.112 89.430 ;
    RECT 27.265 2.280 28.334 89.430 ;
    RECT 28.487 2.280 29.556 89.430 ;
    RECT 29.709 2.280 30.778 89.430 ;
    RECT 30.931 2.280 32.000 89.430 ;
    RECT 32.153 2.280 33.222 89.430 ;
    RECT 33.375 2.280 34.444 89.430 ;
    RECT 34.597 2.280 35.666 89.430 ;
    RECT 35.819 2.280 36.888 89.430 ;
    RECT 37.041 2.280 38.110 89.430 ;
    RECT 38.263 2.280 39.332 89.430 ;
    RECT 39.485 2.280 40.554 89.430 ;
    RECT 40.706 2.280 42.599 89.430 ;
  END
END fakeram45_32x96

END LIBRARY
